// Mitsubishi GX Works2 project: TR3FB_sample_MultiConnection   PLC: Q03UDV
// TR3FBサンプルプログラム TCP/IP接続 2台同時制御

PROGRAM MAIN
VAR
  Connect_1 : P+TAKAYA-TR3-E_Connect;
  Connect_2 : P+TAKAYA-TR3-E_Connect;
  Disconnect_1 : P+TAKAYA-TR3-E_Disconnect;
  Disconnect_2 : P+TAKAYA-TR3-E_Disconnect;
  Inventory_1 : P+TAKAYA-TR3-E_Inventory;
  Inventory_2 : P+TAKAYA-TR3-E_Inventory;
  CallLEDBuzzer_1 : P+TAKAYA-TR3-E_CallLEDBuzzer;
  CallLEDBuzzer_2 : P+TAKAYA-TR3-E_CallLEDBuzzer;
  ReadBytes_1 : P+TAKAYA-TR3-E_ReadBytes;
  WriteBytes_1 : P+TAKAYA-TR3-E_WriteBytes;
  Response_1 : P+TAKAYA-TR3-E_Response;
  Response_2 : P+TAKAYA-TR3-E_Response;
END_VAR
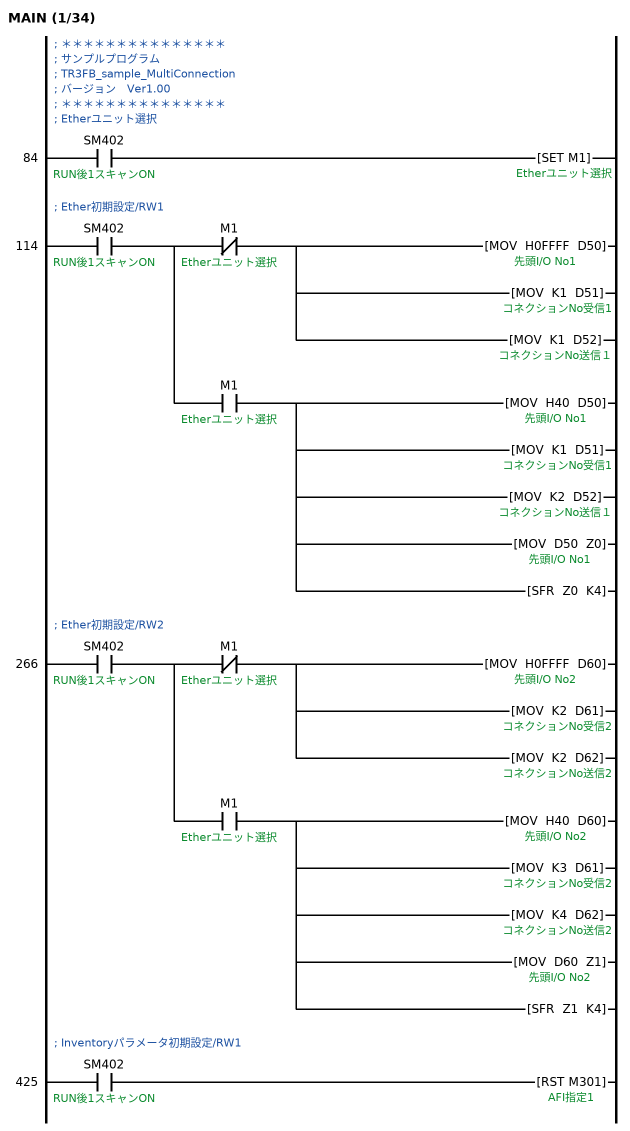
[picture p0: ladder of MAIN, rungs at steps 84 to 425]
; ＊＊＊＊＊＊＊＊＊＊＊＊＊＊＊
; サンプルプログラム
; TR3FB_sample_MultiConnection
; バージョン　Ver1.00
; ＊＊＊＊＊＊＊＊＊＊＊＊＊＊＊
; Etherユニット選択
84    LD      SM402  ; RUN後1スキャンON
      SET     M1  ; Etherユニット選択
        [note] OFF=内蔵Ether　ON=外付けEther
; Ether初期設定/RW1
114   LD      SM402  ; RUN後1スキャンON
      MPS
      ANI     M1  ; Etherユニット選択
      MOV     H0FFFF D50  ; 先頭I/O No1
        [note] 内蔵Ether先頭I/O
      MOV     K1 D51  ; コネクションNo受信1
        [note] 内蔵Ether受信コネクションNo
      MOV     K1 D52  ; コネクションNo送信１
        [note] 内蔵Ether送信コネクションNo
      MPP
      AND     M1  ; Etherユニット選択
      MOV     H40 D50
        [note] 外付Ether先頭I/O
      MOV     K1 D51
        [note] 外付Ether受信コネクションNo
      MOV     K2 D52
        [note] 外付Ether送信コネクションNo
      MOV     D50 Z0
        [note] EtherユニットI/Oアドレス取得
      SFR     Z0 K4
        [note] 4bit右シフトし上位側アドレス取得
; Ether初期設定/RW2
266   LD      SM402  ; RUN後1スキャンON
      MPS
      ANI     M1  ; Etherユニット選択
      MOV     H0FFFF D60  ; 先頭I/O No2
        [note] 内蔵Ether先頭I/O
      MOV     K2 D61  ; コネクションNo受信2
        [note] 内蔵Ether受信コネクションNo
      MOV     K2 D62  ; コネクションNo送信2
        [note] 内蔵Ether送信コネクションNo
      MPP
      AND     M1  ; Etherユニット選択
      MOV     H40 D60
        [note] 外付Ether先頭I/O
      MOV     K3 D61
        [note] 外付Ether受信コネクションNo
      MOV     K4 D62
        [note] 外付Ether送信コネクションNo
      MOV     D60 Z1
        [note] EtherユニットI/Oアドレス取得
      SFR     Z1 K4
        [note] 4bit右シフトし上位側アドレス取得
; Inventoryパラメータ初期設定/RW1
425   LD      SM402  ; RUN後1スキャンON
      RST     M301  ; AFI指定1
        [note] AFI指定：OFF=AFI値を指定しない
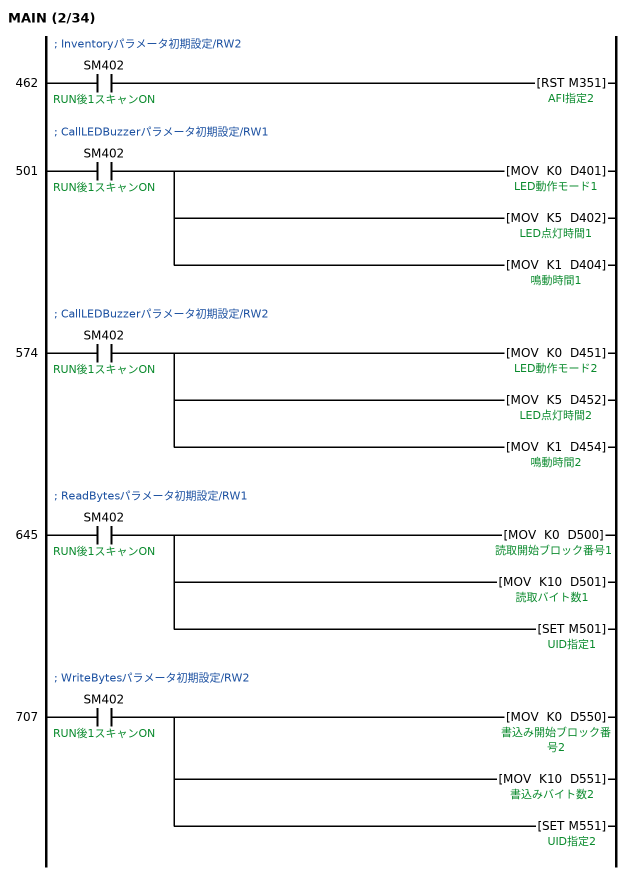
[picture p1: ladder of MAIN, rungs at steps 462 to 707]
; Inventoryパラメータ初期設定/RW2
462   LD      SM402  ; RUN後1スキャンON
      RST     M351  ; AFI指定2
        [note] AFI指定：OFF=AFI値を指定しない
; CallLEDBuzzerパラメータ初期設定/RW1
501   LD      SM402  ; RUN後1スキャンON
      MOV     K0 D401  ; LED動作モード1
        [note] LED動作モード=指定時間の点灯
      MOV     K5 D402  ; LED点灯時間1
        [note] LED点灯時間=1秒（200ms×5）
      MOV     K1 D404  ; 鳴動時間1
        [note] ブザー鳴動時間=鳴動する
; CallLEDBuzzerパラメータ初期設定/RW2
574   LD      SM402  ; RUN後1スキャンON
      MOV     K0 D451  ; LED動作モード2
        [note] LED動作モード=指定時間の点灯
      MOV     K5 D452  ; LED点灯時間2
        [note] LED点灯時間=1秒（200ms×5）
      MOV     K1 D454  ; 鳴動時間2
        [note] ブザー鳴動時間=鳴動する
; ReadBytesパラメータ初期設定/RW1
645   LD      SM402  ; RUN後1スキャンON
      MOV     K0 D500  ; 読取開始ブロック番号1
        [note] 読取開始ブロック番号=0
      MOV     K10 D501  ; 読取バイト数1
        [note] 読取バイト数=10
      SET     M501  ; UID指定1
        [note] UID指定：ON=UIDを指定する
; WriteBytesパラメータ初期設定/RW2
707   LD      SM402  ; RUN後1スキャンON
      MOV     K0 D550  ; 書込み開始ブロック番号2
        [note] 書込み開始ブロック番号=0
      MOV     K10 D551  ; 書込みバイト数2
        [note] 書込みバイト数=10
      SET     M551  ; UID指定2
        [note] UID指定：ON=UIDを指定する
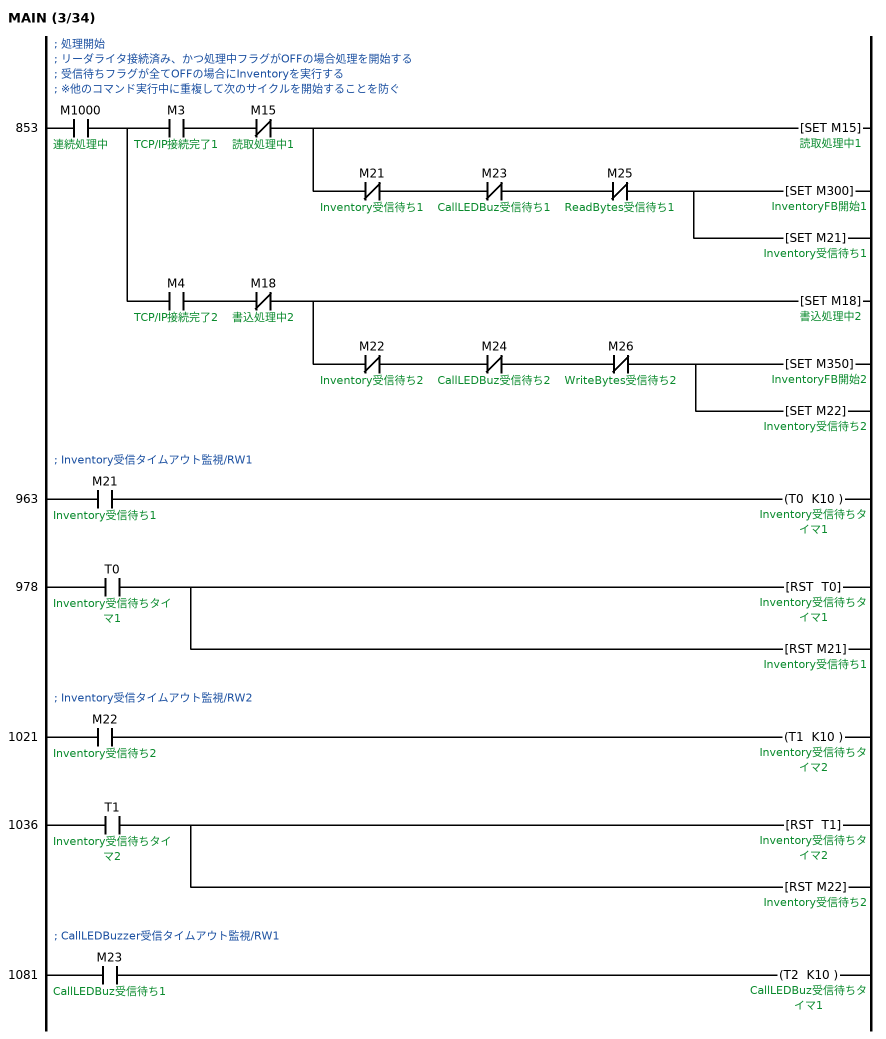
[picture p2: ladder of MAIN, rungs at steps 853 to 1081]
; 処理開始
; リーダライタ接続済み、かつ処理中フラグがOFFの場合処理を開始する
; 受信待ちフラグが全てOFFの場合にInventoryを実行する
; ※他のコマンド実行中に重複して次のサイクルを開始することを防ぐ
853   LD      M1000  ; 連続処理中
      MPS
      AND     M3  ; TCP/IP接続完了1
      ANI     M15  ; 読取処理中1
      SET     M15  ; 読取処理中1
        [note] 読取処理中1：セット
      ANI     M21  ; Inventory受信待ち1
      ANI     M23  ; CallLEDBuz受信待ち1
      ANI     M25  ; ReadBytes受信待ち1
      SET     M300  ; InventoryFB開始1
        [note] Inventory実行
      SET     M21  ; Inventory受信待ち1
        [note] Inventory受信待ち1：セット
      MPP
      AND     M4  ; TCP/IP接続完了2
      ANI     M18  ; 書込処理中2
      SET     M18  ; 書込処理中2
        [note] 書込処理中2：セット
      ANI     M22  ; Inventory受信待ち2
      ANI     M24  ; CallLEDBuz受信待ち2
      ANI     M26  ; WriteBytes受信待ち2
      SET     M350  ; InventoryFB開始2
        [note] Inventory実行
      SET     M22  ; Inventory受信待ち2
        [note] Inventory受信待ち2：セット
; Inventory受信タイムアウト監視/RW1
963   LD      M21  ; Inventory受信待ち1
      OUT     T0 K10  ; Inventory受信待ちタイマ1
        [note] タイマ1秒に設定
978   LD      T0  ; Inventory受信待ちタイマ1
      RST     T0  ; Inventory受信待ちタイマ1
        [note] タイマリセット
      RST     M21  ; Inventory受信待ち1
        [note] フラグリセット
; Inventory受信タイムアウト監視/RW2
1021  LD      M22  ; Inventory受信待ち2
      OUT     T1 K10  ; Inventory受信待ちタイマ2
        [note] タイマ1秒に設定
1036  LD      T1  ; Inventory受信待ちタイマ2
      RST     T1  ; Inventory受信待ちタイマ2
        [note] タイマリセット
      RST     M22  ; Inventory受信待ち2
        [note] フラグリセット
; CallLEDBuzzer受信タイムアウト監視/RW1
1081  LD      M23  ; CallLEDBuz受信待ち1
      OUT     T2 K10  ; CallLEDBuz受信待ちタイマ1
        [note] タイマ1秒に設定
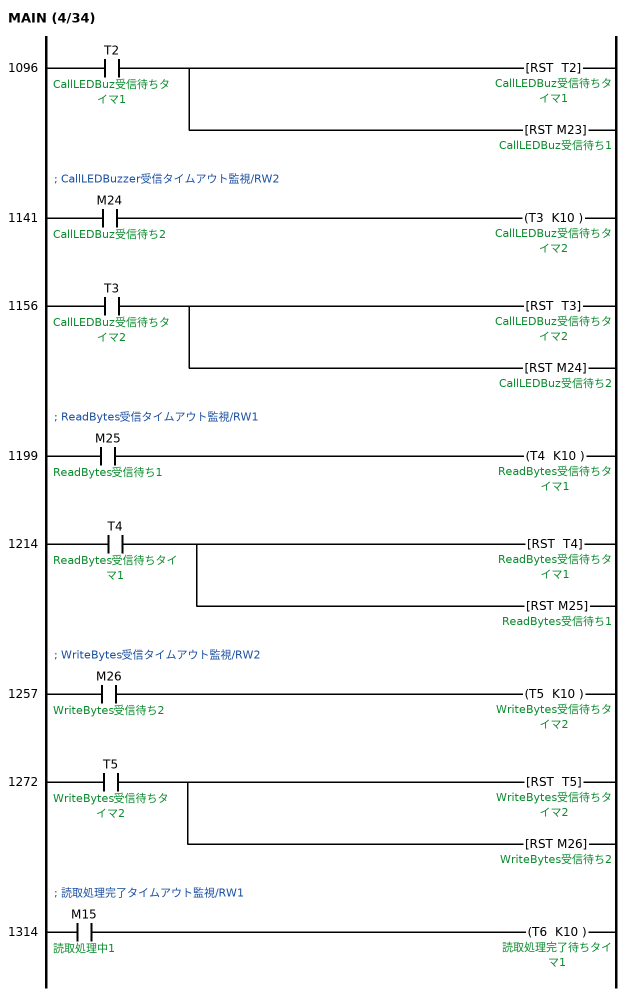
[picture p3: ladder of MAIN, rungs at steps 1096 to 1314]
1096  LD      T2  ; CallLEDBuz受信待ちタイマ1
      RST     T2  ; CallLEDBuz受信待ちタイマ1
        [note] タイマリセット
      RST     M23  ; CallLEDBuz受信待ち1
        [note] フラグリセット
; CallLEDBuzzer受信タイムアウト監視/RW2
1141  LD      M24  ; CallLEDBuz受信待ち2
      OUT     T3 K10  ; CallLEDBuz受信待ちタイマ2
        [note] タイマ1秒に設定
1156  LD      T3  ; CallLEDBuz受信待ちタイマ2
      RST     T3  ; CallLEDBuz受信待ちタイマ2
        [note] タイマリセット
      RST     M24  ; CallLEDBuz受信待ち2
        [note] フラグリセット
; ReadBytes受信タイムアウト監視/RW1
1199  LD      M25  ; ReadBytes受信待ち1
      OUT     T4 K10  ; ReadBytes受信待ちタイマ1
        [note] タイマ1秒に設定
1214  LD      T4  ; ReadBytes受信待ちタイマ1
      RST     T4  ; ReadBytes受信待ちタイマ1
        [note] タイマリセット
      RST     M25  ; ReadBytes受信待ち1
        [note] フラグリセット
; WriteBytes受信タイムアウト監視/RW2
1257  LD      M26  ; WriteBytes受信待ち2
      OUT     T5 K10  ; WriteBytes受信待ちタイマ2
        [note] タイマ1秒に設定
1272  LD      T5  ; WriteBytes受信待ちタイマ2
      RST     T5  ; WriteBytes受信待ちタイマ2
        [note] タイマリセット
      RST     M26  ; WriteBytes受信待ち2
        [note] フラグリセット
; 読取処理完了タイムアウト監視/RW1
1314  LD      M15  ; 読取処理中1
      OUT     T6 K10  ; 読取処理完了待ちタイマ1
        [note] タイマ1秒に設定
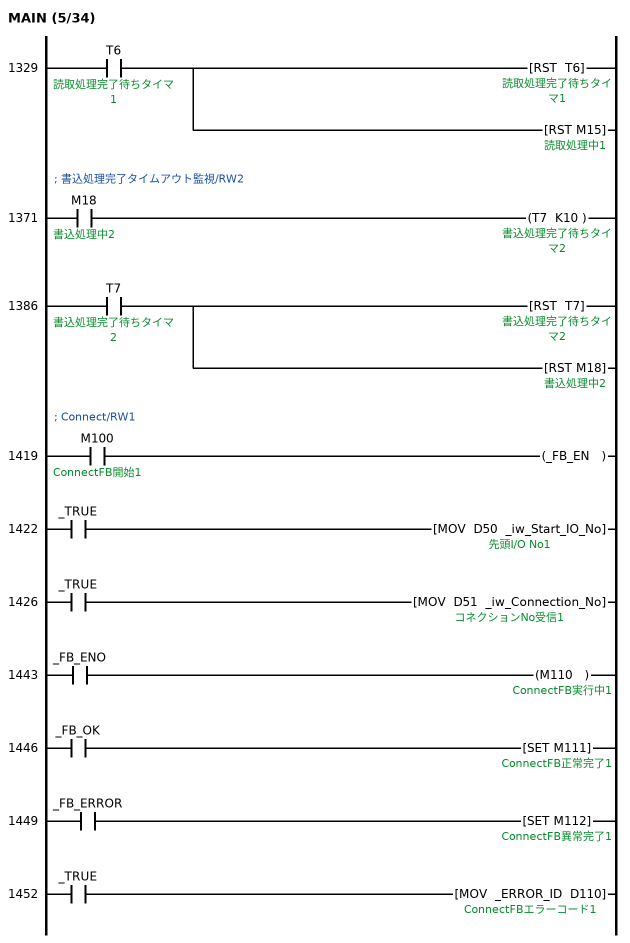
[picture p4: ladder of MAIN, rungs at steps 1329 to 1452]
1329  LD      T6  ; 読取処理完了待ちタイマ1
      RST     T6  ; 読取処理完了待ちタイマ1
        [note] タイマリセット
      RST     M15  ; 読取処理中1
        [note] フラグリセット
; 書込処理完了タイムアウト監視/RW2
1371  LD      M18  ; 書込処理中2
      OUT     T7 K10  ; 書込処理完了待ちタイマ2
        [note] タイマ1秒に設定
1386  LD      T7  ; 書込処理完了待ちタイマ2
      RST     T7  ; 書込処理完了待ちタイマ2
        [note] タイマリセット
      RST     M18  ; 書込処理中2
        [note] フラグリセット
; FB BLK START P+TAKAYA-TR3-E_Connect(Connect_1)
; Connect/RW1
1419  LD      M100  ; ConnectFB開始1
      OUT     _FB_EN
1422  LD      _TRUE
      MOV     D50 _iw_Start_IO_No
1426  LD      _TRUE
      MOV     D51 _iw_Connection_No
; FB START
; FB_NAME P+TAKAYA-TR3-E_Connect
; INSTANCE_NAME Connect_1
; FB IN_B:FB_EN
; FB OUT_FB_ENO:B
; FB IN_W:iw_Start_IO_No
; FB OUT_FB_OK:B
; FB IN_W:iw_Connection_No
; FB OUT_FB_ERROR:B
; FB OUT_ERROR_ID:W
; FB OUT_ob_UNIT_ERROR:B
; FB OUT_ow_UNIT_ERR_CODE:W
; FB END
1443  LD      _FB_ENO
      OUT     M110  ; ConnectFB実行中1
1446  LD      _FB_OK
      SET     M111  ; ConnectFB正常完了1
1449  LD      _FB_ERROR
      SET     M112  ; ConnectFB異常完了1
1452  LD      _TRUE
      MOV     _ERROR_ID D110  ; ConnectFBエラーコード1
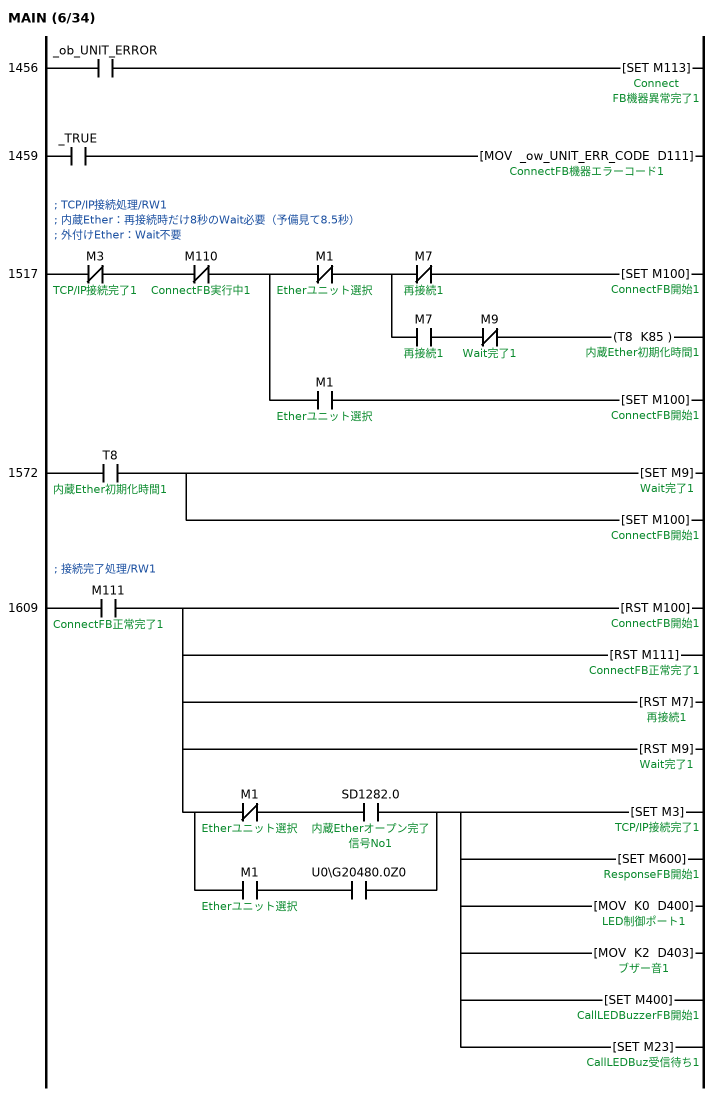
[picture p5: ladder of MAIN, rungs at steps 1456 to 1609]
1456  LD      _ob_UNIT_ERROR
      SET     M113  ; ConnectFB機器異常完了1
1459  LD      _TRUE
      MOV     _ow_UNIT_ERR_CODE D111  ; ConnectFB機器エラーコード1
; FB BLK END
; TCP/IP接続処理/RW1
; 内蔵Ether：再接続時だけ8秒のWait必要（予備見て8.5秒）
; 外付けEther：Wait不要
1517  LDI     M3  ; TCP/IP接続完了1
      ANI     M110  ; ConnectFB実行中1
      MPS
      ANI     M1  ; Etherユニット選択
      MPS
      ANI     M7  ; 再接続1
      SET     M100  ; ConnectFB開始1
        [note] 内蔵Ether初回接続処理
      MPP
      AND     M7  ; 再接続1
      ANI     M9  ; Wait完了1
      OUT     T8 K85  ; 内蔵Ether初期化時間1
        [note] 内蔵Ether再接続Wait処理
      MPP
      AND     M1  ; Etherユニット選択
      SET     M100  ; ConnectFB開始1
        [note] 外付Ether接続処理
1572  LD      T8  ; 内蔵Ether初期化時間1
      SET     M9  ; Wait完了1
        [note] Wait完了フラグをセット
      SET     M100  ; ConnectFB開始1
        [note] Wait完了後に再接続
; 接続完了処理/RW1
1609  LD      M111  ; ConnectFB正常完了1
      RST     M100  ; ConnectFB開始1
        [note] FB動作停止
      RST     M111  ; ConnectFB正常完了1
        [note] フラグリセット
      RST     M7  ; 再接続1
        [note] フラグリセット
      RST     M9  ; Wait完了1
        [note] フラグリセット
      LDI     M1  ; Etherユニット選択
      AND     SD1282.0  ; 内蔵Etherオープン完了信号No1
      LD      M1  ; Etherユニット選択
      AND     U0\G20480.0Z0
      ORB
      ANB
      SET     M3  ; TCP/IP接続完了1
        [note] TCP/IP接続完了：セット
      SET     M600  ; ResponseFB開始1
        [note] 受信処理開始
      MOV     K0 D400  ; LED制御ポート1
        [note] LED制御ポート=0/LED制御なし
      MOV     K2 D403  ; ブザー音1
        [note] ブザー音=2/ピッピー
      SET     M400  ; CallLEDBuzzerFB開始1
        [note] CallLEDBuzzer実行
      SET     M23  ; CallLEDBuz受信待ち1
        [note] CallLEDBuz受信待ち1：セット
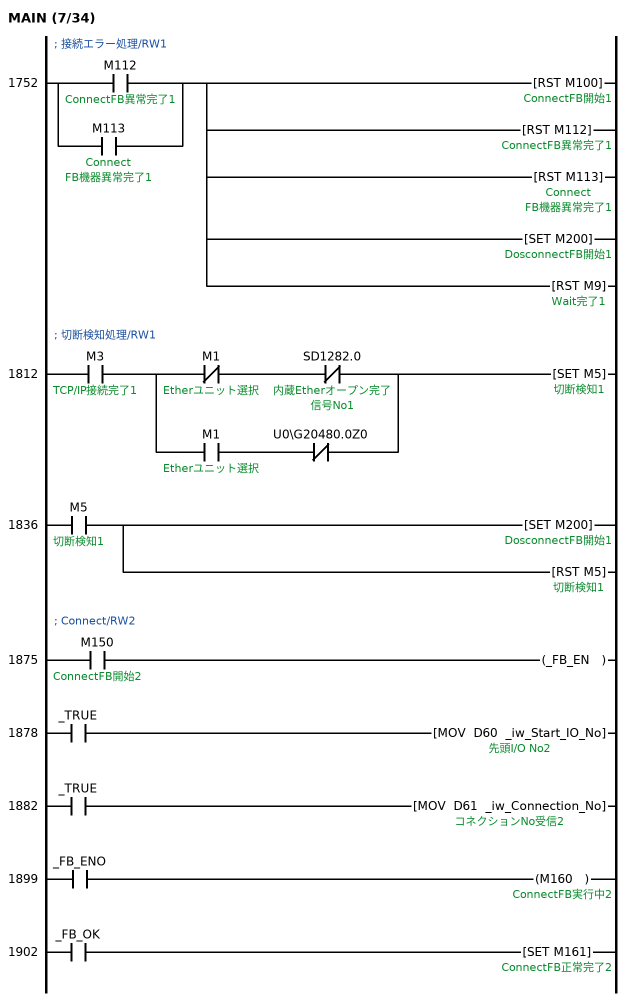
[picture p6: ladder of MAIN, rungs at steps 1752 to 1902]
; 接続エラー処理/RW1
1752  LD      M112  ; ConnectFB異常完了1
      OR      M113  ; ConnectFB機器異常完了1
      RST     M100  ; ConnectFB開始1
        [note] FB動作停止
      RST     M112  ; ConnectFB異常完了1
        [note] フラグリセット
      RST     M113  ; ConnectFB機器異常完了1
        [note] フラグリセット
      SET     M200  ; DosconnectFB開始1
        [note] 切断処理を実行
      RST     M9  ; Wait完了1
        [note] フラグリセット
; 切断検知処理/RW1
1812  LD      M3  ; TCP/IP接続完了1
      LDI     M1  ; Etherユニット選択
      ANI     SD1282.0  ; 内蔵Etherオープン完了信号No1
      LD      M1  ; Etherユニット選択
      ANI     U0\G20480.0Z0
      ORB
      ANB
      SET     M5  ; 切断検知1
        [note] 切断検知フラグをセット
1836  LD      M5  ; 切断検知1
      SET     M200  ; DosconnectFB開始1
        [note] 切断処理（再接続するために必要）
      RST     M5  ; 切断検知1
        [note] フラグリセット
; FB BLK START P+TAKAYA-TR3-E_Connect(Connect_2)
; Connect/RW2
1875  LD      M150  ; ConnectFB開始2
      OUT     _FB_EN
1878  LD      _TRUE
      MOV     D60 _iw_Start_IO_No
1882  LD      _TRUE
      MOV     D61 _iw_Connection_No
; FB START
; FB_NAME P+TAKAYA-TR3-E_Connect
; INSTANCE_NAME Connect_2
; FB IN_B:FB_EN
; FB OUT_FB_ENO:B
; FB IN_W:iw_Start_IO_No
; FB OUT_FB_OK:B
; FB IN_W:iw_Connection_No
; FB OUT_FB_ERROR:B
; FB OUT_ERROR_ID:W
; FB OUT_ob_UNIT_ERROR:B
; FB OUT_ow_UNIT_ERR_CODE:W
; FB END
1899  LD      _FB_ENO
      OUT     M160  ; ConnectFB実行中2
1902  LD      _FB_OK
      SET     M161  ; ConnectFB正常完了2
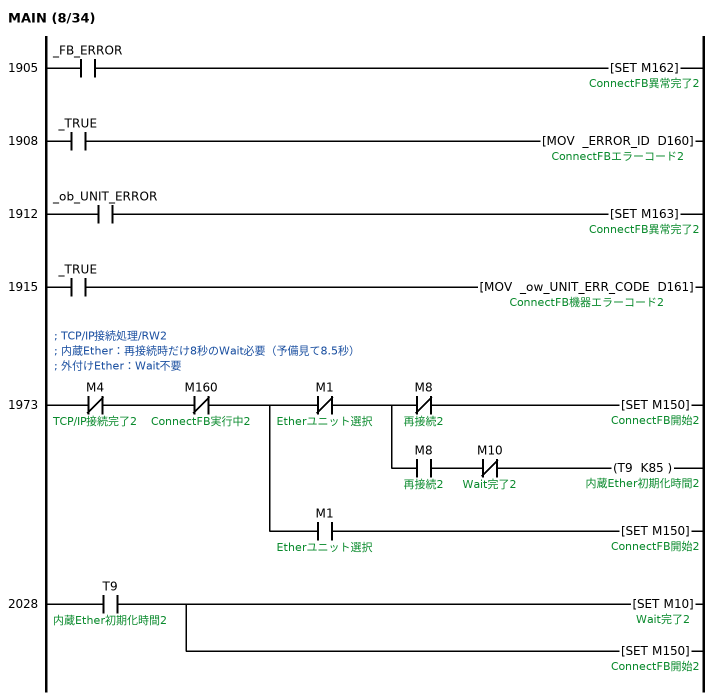
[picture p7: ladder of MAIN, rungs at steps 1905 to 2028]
1905  LD      _FB_ERROR
      SET     M162  ; ConnectFB異常完了2
1908  LD      _TRUE
      MOV     _ERROR_ID D160  ; ConnectFBエラーコード2
1912  LD      _ob_UNIT_ERROR
      SET     M163  ; ConnectFB異常完了2
1915  LD      _TRUE
      MOV     _ow_UNIT_ERR_CODE D161  ; ConnectFB機器エラーコード2
; FB BLK END
; TCP/IP接続処理/RW2
; 内蔵Ether：再接続時だけ8秒のWait必要（予備見て8.5秒）
; 外付けEther：Wait不要
1973  LDI     M4  ; TCP/IP接続完了2
      ANI     M160  ; ConnectFB実行中2
      MPS
      ANI     M1  ; Etherユニット選択
      MPS
      ANI     M8  ; 再接続2
      SET     M150  ; ConnectFB開始2
        [note] 内蔵Ether初回接続処理
      MPP
      AND     M8  ; 再接続2
      ANI     M10  ; Wait完了2
      OUT     T9 K85  ; 内蔵Ether初期化時間2
        [note] 内蔵Ether再接続Wait処理
      MPP
      AND     M1  ; Etherユニット選択
      SET     M150  ; ConnectFB開始2
        [note] 外付Ether接続処理
2028  LD      T9  ; 内蔵Ether初期化時間2
      SET     M10  ; Wait完了2
        [note] Wait完了フラグをセット
      SET     M150  ; ConnectFB開始2
        [note] Wait完了後に再接続
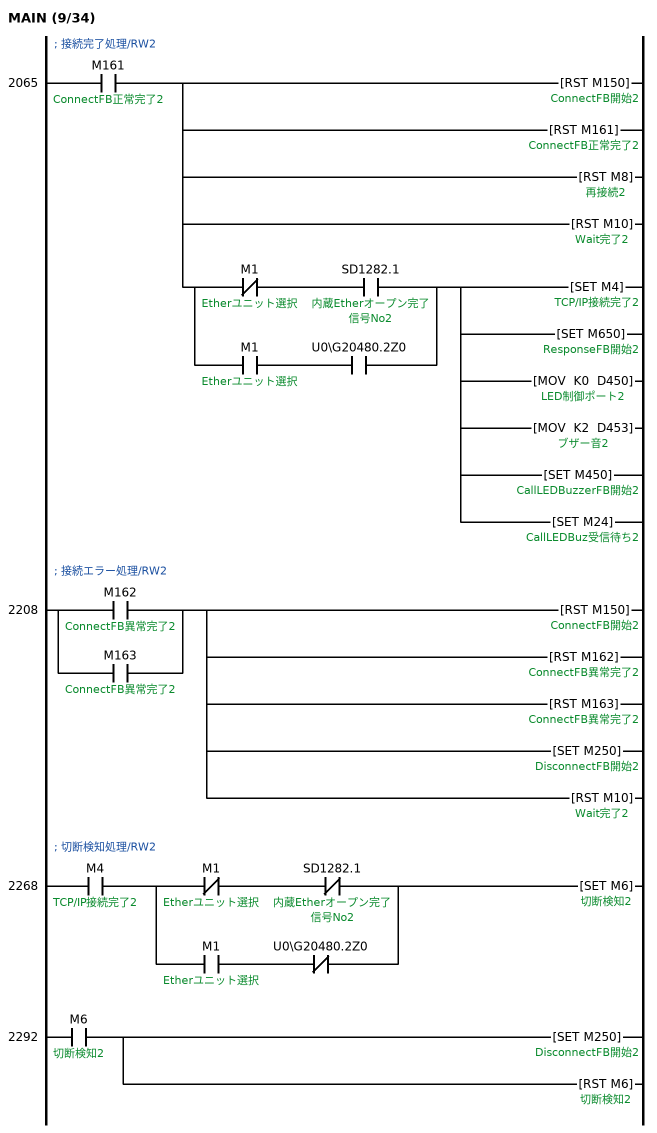
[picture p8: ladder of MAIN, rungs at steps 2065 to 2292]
; 接続完了処理/RW2
2065  LD      M161  ; ConnectFB正常完了2
      RST     M150  ; ConnectFB開始2
        [note] FB動作停止
      RST     M161  ; ConnectFB正常完了2
        [note] フラグリセット
      RST     M8  ; 再接続2
        [note] フラグリセット
      RST     M10  ; Wait完了2
        [note] フラグリセット
      LDI     M1  ; Etherユニット選択
      AND     SD1282.1  ; 内蔵Etherオープン完了信号No2
      LD      M1  ; Etherユニット選択
      AND     U0\G20480.2Z0
      ORB
      ANB
      SET     M4  ; TCP/IP接続完了2
        [note] TCP/IP接続完了：セット
      SET     M650  ; ResponseFB開始2
        [note] 受信処理開始
      MOV     K0 D450  ; LED制御ポート2
        [note] LED制御ポート=0/LED制御なし
      MOV     K2 D453  ; ブザー音2
        [note] ブザー音=2/ピッピー
      SET     M450  ; CallLEDBuzzerFB開始2
        [note] CallLEDBuzzer実行
      SET     M24  ; CallLEDBuz受信待ち2
        [note] CallLEDBuz受信待ち2：セット
; 接続エラー処理/RW2
2208  LD      M162  ; ConnectFB異常完了2
      OR      M163  ; ConnectFB異常完了2
      RST     M150  ; ConnectFB開始2
        [note] FB動作停止
      RST     M162  ; ConnectFB異常完了2
        [note] フラグリセット
      RST     M163  ; ConnectFB異常完了2
        [note] フラグリセット
      SET     M250  ; DisconnectFB開始2
        [note] 切断処理を実行
      RST     M10  ; Wait完了2
        [note] フラグリセット
; 切断検知処理/RW2
2268  LD      M4  ; TCP/IP接続完了2
      LDI     M1  ; Etherユニット選択
      ANI     SD1282.1  ; 内蔵Etherオープン完了信号No2
      LD      M1  ; Etherユニット選択
      ANI     U0\G20480.2Z0
      ORB
      ANB
      SET     M6  ; 切断検知2
        [note] 切断検知フラグをセット
2292  LD      M6  ; 切断検知2
      SET     M250  ; DisconnectFB開始2
        [note] 切断処理（再接続するために必要）
      RST     M6  ; 切断検知2
        [note] フラグリセット
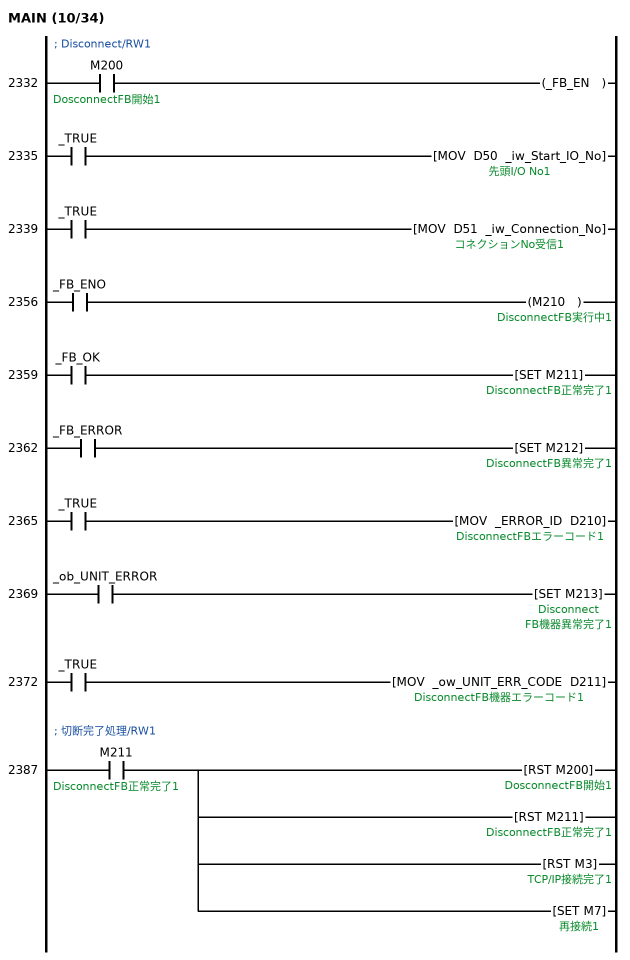
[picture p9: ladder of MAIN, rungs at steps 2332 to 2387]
; FB BLK START P+TAKAYA-TR3-E_Disconnect(Disconnect_1)
; Disconnect/RW1
2332  LD      M200  ; DosconnectFB開始1
      OUT     _FB_EN
2335  LD      _TRUE
      MOV     D50 _iw_Start_IO_No
2339  LD      _TRUE
      MOV     D51 _iw_Connection_No
; FB START
; FB_NAME P+TAKAYA-TR3-E_Disconnect
; INSTANCE_NAME Disconnect_1
; FB IN_B:FB_EN
; FB OUT_FB_ENO:B
; FB IN_W:iw_Start_IO_No
; FB OUT_FB_OK:B
; FB IN_W:iw_Connection_No
; FB OUT_FB_ERROR:B
; FB OUT_ERROR_ID:W
; FB OUT_ob_UNIT_ERROR:B
; FB OUT_ow_UNIT_ERR_CODE:W
; FB END
2356  LD      _FB_ENO
      OUT     M210  ; DisconnectFB実行中1
2359  LD      _FB_OK
      SET     M211  ; DisconnectFB正常完了1
2362  LD      _FB_ERROR
      SET     M212  ; DisconnectFB異常完了1
2365  LD      _TRUE
      MOV     _ERROR_ID D210  ; DisconnectFBエラーコード1
2369  LD      _ob_UNIT_ERROR
      SET     M213  ; DisconnectFB機器異常完了1
2372  LD      _TRUE
      MOV     _ow_UNIT_ERR_CODE D211  ; DisconnectFB機器エラーコード1
; FB BLK END
; 切断完了処理/RW1
2387  LD      M211  ; DisconnectFB正常完了1
      RST     M200  ; DosconnectFB開始1
        [note] FB動作停止
      RST     M211  ; DisconnectFB正常完了1
        [note] フラグリセット
      RST     M3  ; TCP/IP接続完了1
        [note] フラグリセット
      SET     M7  ; 再接続1
        [note] 再接続：セット
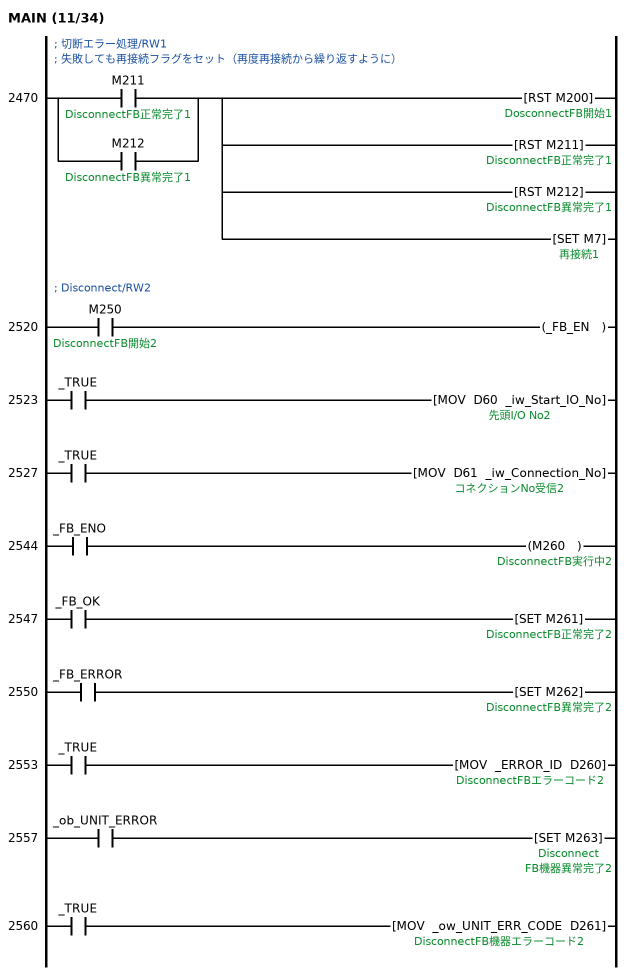
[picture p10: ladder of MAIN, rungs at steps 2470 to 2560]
; 切断エラー処理/RW1
; 失敗しても再接続フラグをセット（再度再接続から繰り返すように）
2470  LD      M211  ; DisconnectFB正常完了1
      OR      M212  ; DisconnectFB異常完了1
      RST     M200  ; DosconnectFB開始1
        [note] FB動作停止
      RST     M211  ; DisconnectFB正常完了1
        [note] フラグリセット
      RST     M212  ; DisconnectFB異常完了1
        [note] フラグリセット
      SET     M7  ; 再接続1
        [note] 再接続：セット
; FB BLK START P+TAKAYA-TR3-E_Disconnect(Disconnect_2)
; Disconnect/RW2
2520  LD      M250  ; DisconnectFB開始2
      OUT     _FB_EN
2523  LD      _TRUE
      MOV     D60 _iw_Start_IO_No
2527  LD      _TRUE
      MOV     D61 _iw_Connection_No
; FB START
; FB_NAME P+TAKAYA-TR3-E_Disconnect
; INSTANCE_NAME Disconnect_2
; FB IN_B:FB_EN
; FB OUT_FB_ENO:B
; FB IN_W:iw_Start_IO_No
; FB OUT_FB_OK:B
; FB IN_W:iw_Connection_No
; FB OUT_FB_ERROR:B
; FB OUT_ERROR_ID:W
; FB OUT_ob_UNIT_ERROR:B
; FB OUT_ow_UNIT_ERR_CODE:W
; FB END
2544  LD      _FB_ENO
      OUT     M260  ; DisconnectFB実行中2
2547  LD      _FB_OK
      SET     M261  ; DisconnectFB正常完了2
2550  LD      _FB_ERROR
      SET     M262  ; DisconnectFB異常完了2
2553  LD      _TRUE
      MOV     _ERROR_ID D260  ; DisconnectFBエラーコード2
2557  LD      _ob_UNIT_ERROR
      SET     M263  ; DisconnectFB機器異常完了2
2560  LD      _TRUE
      MOV     _ow_UNIT_ERR_CODE D261  ; DisconnectFB機器エラーコード2
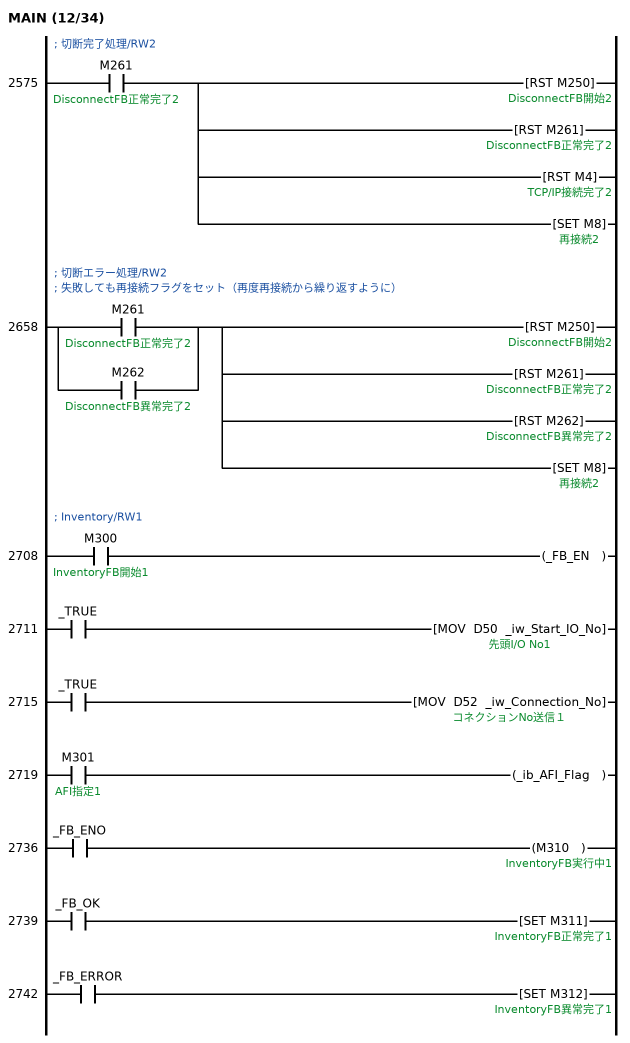
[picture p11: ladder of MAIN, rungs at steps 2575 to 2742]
; FB BLK END
; 切断完了処理/RW2
2575  LD      M261  ; DisconnectFB正常完了2
      RST     M250  ; DisconnectFB開始2
        [note] FB動作停止
      RST     M261  ; DisconnectFB正常完了2
        [note] フラグリセット
      RST     M4  ; TCP/IP接続完了2
        [note] フラグリセット
      SET     M8  ; 再接続2
        [note] 再接続：セット
; 切断エラー処理/RW2
; 失敗しても再接続フラグをセット（再度再接続から繰り返すように）
2658  LD      M261  ; DisconnectFB正常完了2
      OR      M262  ; DisconnectFB異常完了2
      RST     M250  ; DisconnectFB開始2
        [note] FB動作停止
      RST     M261  ; DisconnectFB正常完了2
        [note] フラグリセット
      RST     M262  ; DisconnectFB異常完了2
        [note] フラグリセット
      SET     M8  ; 再接続2
        [note] 再接続：セット
; FB BLK START P+TAKAYA-TR3-E_Inventory(Inventory_1)
; Inventory/RW1
2708  LD      M300  ; InventoryFB開始1
      OUT     _FB_EN
2711  LD      _TRUE
      MOV     D50 _iw_Start_IO_No
2715  LD      _TRUE
      MOV     D52 _iw_Connection_No
2719  LD      M301  ; AFI指定1
      OUT     _ib_AFI_Flag
; FB START
; FB_NAME P+TAKAYA-TR3-E_Inventory
; INSTANCE_NAME Inventory_1
; FB IN_B:FB_EN
; FB OUT_FB_ENO:B
; FB IN_W:iw_Start_IO_No
; FB OUT_FB_OK:B
; FB IN_W:iw_Connection_No
; FB OUT_FB_ERROR:B
; FB IN_B:ib_AFI_Flag
; FB OUT_ERROR_ID:W
; FB OUT_ob_UNIT_ERROR:B
; FB OUT_ow_UNIT_ERR_CODE:W
; FB END
2736  LD      _FB_ENO
      OUT     M310  ; InventoryFB実行中1
2739  LD      _FB_OK
      SET     M311  ; InventoryFB正常完了1
2742  LD      _FB_ERROR
      SET     M312  ; InventoryFB異常完了1
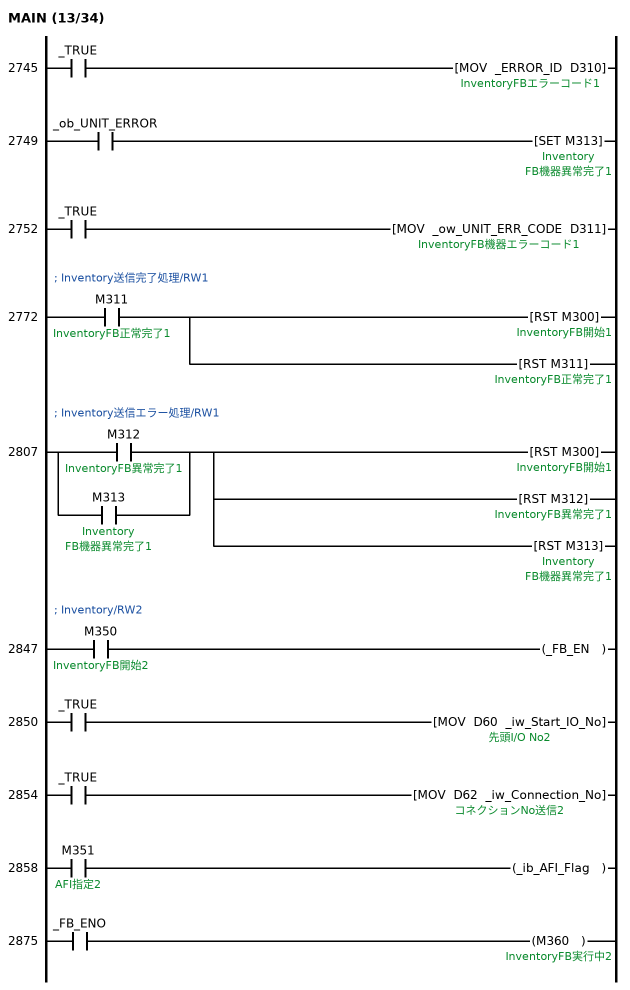
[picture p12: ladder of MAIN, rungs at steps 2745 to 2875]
2745  LD      _TRUE
      MOV     _ERROR_ID D310  ; InventoryFBエラーコード1
2749  LD      _ob_UNIT_ERROR
      SET     M313  ; InventoryFB機器異常完了1
2752  LD      _TRUE
      MOV     _ow_UNIT_ERR_CODE D311  ; InventoryFB機器エラーコード1
; FB BLK END
; Inventory送信完了処理/RW1
2772  LD      M311  ; InventoryFB正常完了1
      RST     M300  ; InventoryFB開始1
        [note] FB動作停止
      RST     M311  ; InventoryFB正常完了1
        [note] フラグリセット
; Inventory送信エラー処理/RW1
2807  LD      M312  ; InventoryFB異常完了1
      OR      M313  ; InventoryFB機器異常完了1
      RST     M300  ; InventoryFB開始1
        [note] FB動作停止
      RST     M312  ; InventoryFB異常完了1
        [note] フラグリセット
      RST     M313  ; InventoryFB機器異常完了1
        [note] フラグリセット
; FB BLK START P+TAKAYA-TR3-E_Inventory(Inventory_2)
; Inventory/RW2
2847  LD      M350  ; InventoryFB開始2
      OUT     _FB_EN
2850  LD      _TRUE
      MOV     D60 _iw_Start_IO_No
2854  LD      _TRUE
      MOV     D62 _iw_Connection_No
2858  LD      M351  ; AFI指定2
      OUT     _ib_AFI_Flag
; FB START
; FB_NAME P+TAKAYA-TR3-E_Inventory
; INSTANCE_NAME Inventory_2
; FB IN_B:FB_EN
; FB OUT_FB_ENO:B
; FB IN_W:iw_Start_IO_No
; FB OUT_FB_OK:B
; FB IN_W:iw_Connection_No
; FB OUT_FB_ERROR:B
; FB IN_B:ib_AFI_Flag
; FB OUT_ERROR_ID:W
; FB OUT_ob_UNIT_ERROR:B
; FB OUT_ow_UNIT_ERR_CODE:W
; FB END
2875  LD      _FB_ENO
      OUT     M360  ; InventoryFB実行中2
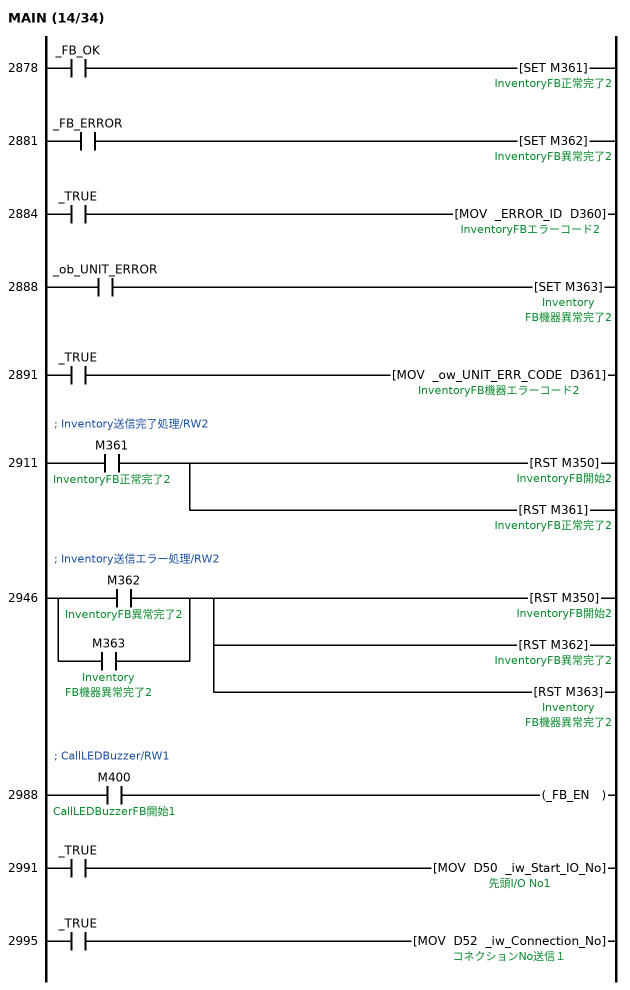
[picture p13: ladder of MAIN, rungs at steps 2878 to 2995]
2878  LD      _FB_OK
      SET     M361  ; InventoryFB正常完了2
2881  LD      _FB_ERROR
      SET     M362  ; InventoryFB異常完了2
2884  LD      _TRUE
      MOV     _ERROR_ID D360  ; InventoryFBエラーコード2
2888  LD      _ob_UNIT_ERROR
      SET     M363  ; InventoryFB機器異常完了2
2891  LD      _TRUE
      MOV     _ow_UNIT_ERR_CODE D361  ; InventoryFB機器エラーコード2
; FB BLK END
; Inventory送信完了処理/RW2
2911  LD      M361  ; InventoryFB正常完了2
      RST     M350  ; InventoryFB開始2
        [note] FB動作停止
      RST     M361  ; InventoryFB正常完了2
        [note] フラグリセット
; Inventory送信エラー処理/RW2
2946  LD      M362  ; InventoryFB異常完了2
      OR      M363  ; InventoryFB機器異常完了2
      RST     M350  ; InventoryFB開始2
        [note] FB動作停止
      RST     M362  ; InventoryFB異常完了2
        [note] フラグリセット
      RST     M363  ; InventoryFB機器異常完了2
        [note] フラグリセット
; FB BLK START P+TAKAYA-TR3-E_CallLEDBuzzer(CallLEDBuzzer_1)
; CallLEDBuzzer/RW1
2988  LD      M400  ; CallLEDBuzzerFB開始1
      OUT     _FB_EN
2991  LD      _TRUE
      MOV     D50 _iw_Start_IO_No
2995  LD      _TRUE
      MOV     D52 _iw_Connection_No
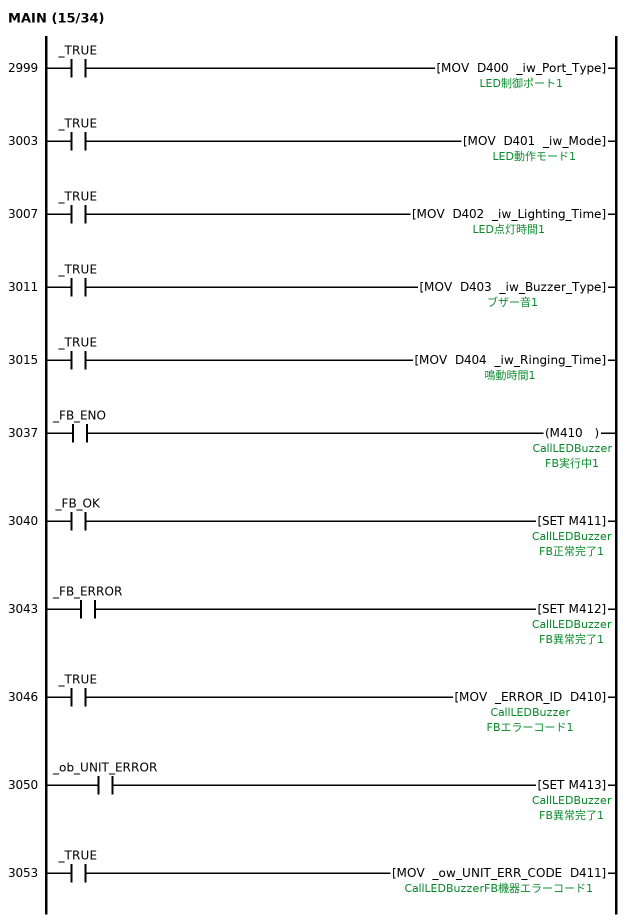
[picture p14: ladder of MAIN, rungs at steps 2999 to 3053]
2999  LD      _TRUE
      MOV     D400 _iw_Port_Type
3003  LD      _TRUE
      MOV     D401 _iw_Mode
3007  LD      _TRUE
      MOV     D402 _iw_Lighting_Time
3011  LD      _TRUE
      MOV     D403 _iw_Buzzer_Type
3015  LD      _TRUE
      MOV     D404 _iw_Ringing_Time
; FB START
; FB_NAME P+TAKAYA-TR3-E_CallLEDBuzzer
; INSTANCE_NAME CallLEDBuzzer_1
; FB IN_B:FB_EN
; FB OUT_FB_ENO:B
; FB IN_W:iw_Start_IO_No
; FB OUT_FB_OK:B
; FB IN_W:iw_Connection_No
; FB OUT_FB_ERROR:B
; FB IN_W:iw_Port_Type
; FB OUT_ERROR_ID:W
; FB IN_W:iw_Mode
; FB OUT_ob_UNIT_ERROR:B
; FB IN_W:iw_Lighting_Time
; FB OUT_ow_UNIT_ERR_CODE:W
; FB IN_W:iw_Buzzer_Type
; FB IN_W:iw_Ringing_Time
; FB END
3037  LD      _FB_ENO
      OUT     M410  ; CallLEDBuzzerFB実行中1
3040  LD      _FB_OK
      SET     M411  ; CallLEDBuzzerFB正常完了1
3043  LD      _FB_ERROR
      SET     M412  ; CallLEDBuzzerFB異常完了1
3046  LD      _TRUE
      MOV     _ERROR_ID D410  ; CallLEDBuzzerFBエラーコード1
3050  LD      _ob_UNIT_ERROR
      SET     M413  ; CallLEDBuzzerFB異常完了1
3053  LD      _TRUE
      MOV     _ow_UNIT_ERR_CODE D411  ; CallLEDBuzzerFB機器エラーコード1
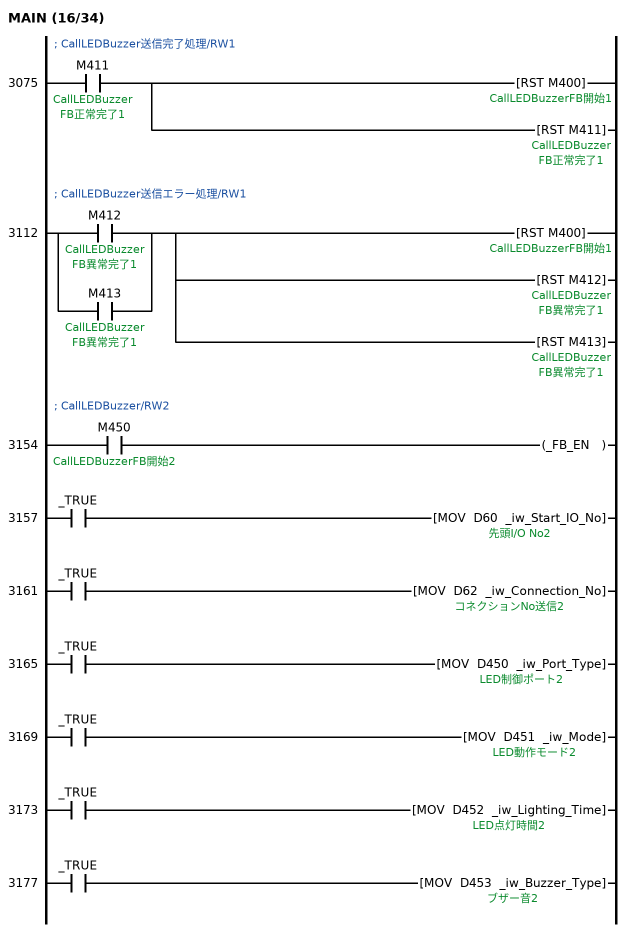
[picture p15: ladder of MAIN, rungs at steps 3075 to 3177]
; FB BLK END
; CallLEDBuzzer送信完了処理/RW1
3075  LD      M411  ; CallLEDBuzzerFB正常完了1
      RST     M400  ; CallLEDBuzzerFB開始1
        [note] FB動作停止
      RST     M411  ; CallLEDBuzzerFB正常完了1
        [note] フラグリセット
; CallLEDBuzzer送信エラー処理/RW1
3112  LD      M412  ; CallLEDBuzzerFB異常完了1
      OR      M413  ; CallLEDBuzzerFB異常完了1
      RST     M400  ; CallLEDBuzzerFB開始1
        [note] FB動作停止
      RST     M412  ; CallLEDBuzzerFB異常完了1
        [note] フラグリセット
      RST     M413  ; CallLEDBuzzerFB異常完了1
        [note] フラグリセット
; FB BLK START P+TAKAYA-TR3-E_CallLEDBuzzer(CallLEDBuzzer_2)
; CallLEDBuzzer/RW2
3154  LD      M450  ; CallLEDBuzzerFB開始2
      OUT     _FB_EN
3157  LD      _TRUE
      MOV     D60 _iw_Start_IO_No
3161  LD      _TRUE
      MOV     D62 _iw_Connection_No
3165  LD      _TRUE
      MOV     D450 _iw_Port_Type
3169  LD      _TRUE
      MOV     D451 _iw_Mode
3173  LD      _TRUE
      MOV     D452 _iw_Lighting_Time
3177  LD      _TRUE
      MOV     D453 _iw_Buzzer_Type
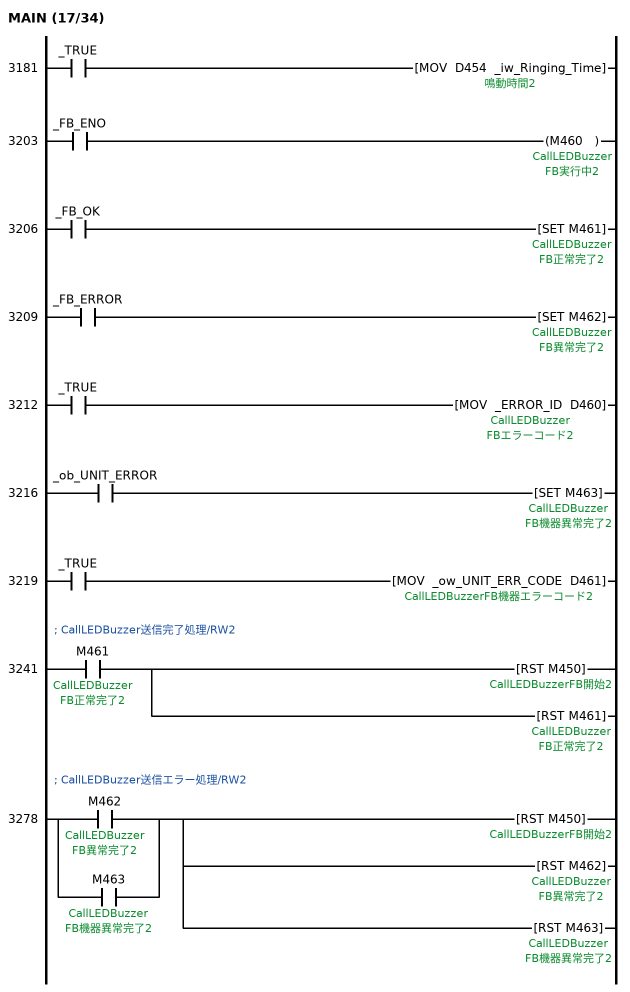
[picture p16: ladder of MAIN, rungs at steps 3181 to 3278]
3181  LD      _TRUE
      MOV     D454 _iw_Ringing_Time
; FB START
; FB_NAME P+TAKAYA-TR3-E_CallLEDBuzzer
; INSTANCE_NAME CallLEDBuzzer_2
; FB IN_B:FB_EN
; FB OUT_FB_ENO:B
; FB IN_W:iw_Start_IO_No
; FB OUT_FB_OK:B
; FB IN_W:iw_Connection_No
; FB OUT_FB_ERROR:B
; FB IN_W:iw_Port_Type
; FB OUT_ERROR_ID:W
; FB IN_W:iw_Mode
; FB OUT_ob_UNIT_ERROR:B
; FB IN_W:iw_Lighting_Time
; FB OUT_ow_UNIT_ERR_CODE:W
; FB IN_W:iw_Buzzer_Type
; FB IN_W:iw_Ringing_Time
; FB END
3203  LD      _FB_ENO
      OUT     M460  ; CallLEDBuzzerFB実行中2
3206  LD      _FB_OK
      SET     M461  ; CallLEDBuzzerFB正常完了2
3209  LD      _FB_ERROR
      SET     M462  ; CallLEDBuzzerFB異常完了2
3212  LD      _TRUE
      MOV     _ERROR_ID D460  ; CallLEDBuzzerFBエラーコード2
3216  LD      _ob_UNIT_ERROR
      SET     M463  ; CallLEDBuzzerFB機器異常完了2
3219  LD      _TRUE
      MOV     _ow_UNIT_ERR_CODE D461  ; CallLEDBuzzerFB機器エラーコード2
; FB BLK END
; CallLEDBuzzer送信完了処理/RW2
3241  LD      M461  ; CallLEDBuzzerFB正常完了2
      RST     M450  ; CallLEDBuzzerFB開始2
        [note] FB動作停止
      RST     M461  ; CallLEDBuzzerFB正常完了2
        [note] フラグリセット
; CallLEDBuzzer送信エラー処理/RW2
3278  LD      M462  ; CallLEDBuzzerFB異常完了2
      OR      M463  ; CallLEDBuzzerFB機器異常完了2
      RST     M450  ; CallLEDBuzzerFB開始2
        [note] FB動作停止
      RST     M462  ; CallLEDBuzzerFB異常完了2
        [note] フラグリセット
      RST     M463  ; CallLEDBuzzerFB機器異常完了2
        [note] フラグリセット
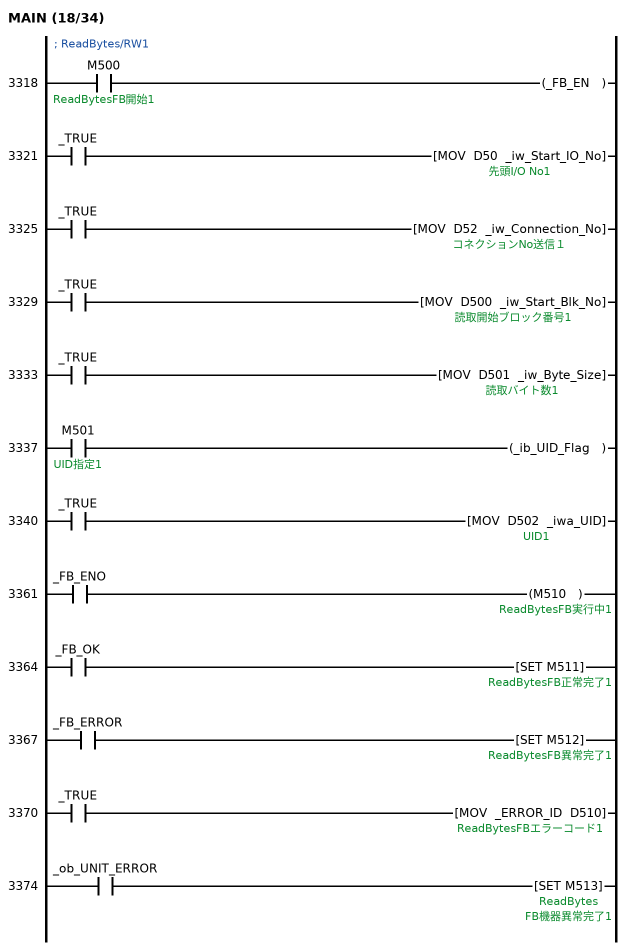
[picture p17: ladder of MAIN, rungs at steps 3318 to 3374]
; FB BLK START P+TAKAYA-TR3-E_ReadBytes(ReadBytes_1)
; ReadBytes/RW1
3318  LD      M500  ; ReadBytesFB開始1
      OUT     _FB_EN
3321  LD      _TRUE
      MOV     D50 _iw_Start_IO_No
3325  LD      _TRUE
      MOV     D52 _iw_Connection_No
3329  LD      _TRUE
      MOV     D500 _iw_Start_Blk_No
3333  LD      _TRUE
      MOV     D501 _iw_Byte_Size
3337  LD      M501  ; UID指定1
      OUT     _ib_UID_Flag
3340  LD      _TRUE
      MOV     D502 _iwa_UID  ; UID1
; FB START
; FB_NAME P+TAKAYA-TR3-E_ReadBytes
; INSTANCE_NAME ReadBytes_1
; FB IN_B:FB_EN
; FB OUT_FB_ENO:B
; FB IN_W:iw_Start_IO_No
; FB OUT_FB_OK:B
; FB IN_W:iw_Connection_No
; FB OUT_FB_ERROR:B
; FB IN_W:iw_Start_Blk_No
; FB OUT_ERROR_ID:W
; FB IN_W:iw_Byte_Size
; FB OUT_ob_UNIT_ERROR:B
; FB IN_B:ib_UID_Flag
; FB OUT_ow_UNIT_ERR_CODE:W
; FB IN_W:iwa_UID
; FB END
3361  LD      _FB_ENO
      OUT     M510  ; ReadBytesFB実行中1
3364  LD      _FB_OK
      SET     M511  ; ReadBytesFB正常完了1
3367  LD      _FB_ERROR
      SET     M512  ; ReadBytesFB異常完了1
3370  LD      _TRUE
      MOV     _ERROR_ID D510  ; ReadBytesFBエラーコード1
3374  LD      _ob_UNIT_ERROR
      SET     M513  ; ReadBytesFB機器異常完了1
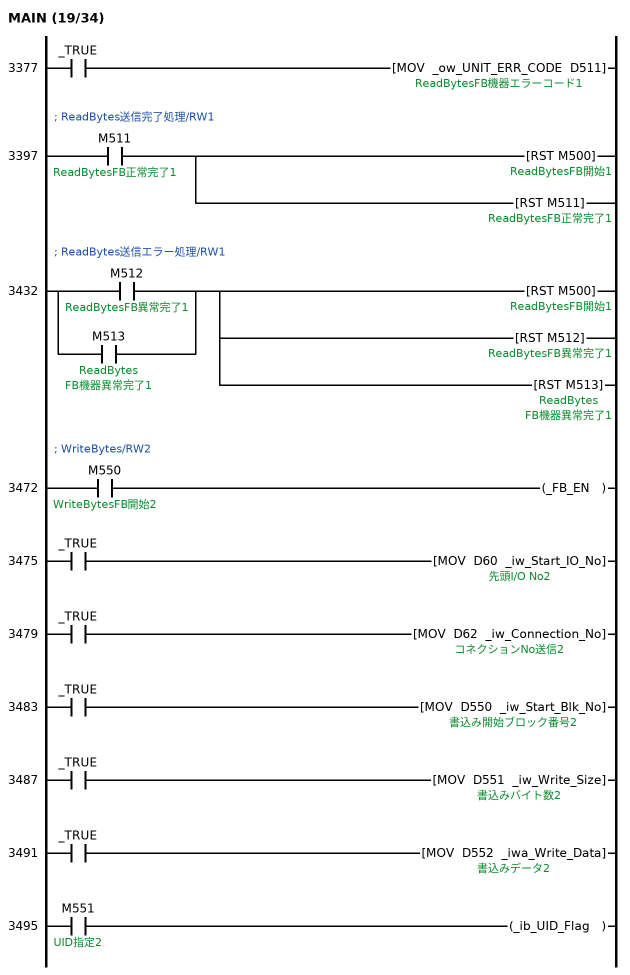
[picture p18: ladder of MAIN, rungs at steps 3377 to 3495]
3377  LD      _TRUE
      MOV     _ow_UNIT_ERR_CODE D511  ; ReadBytesFB機器エラーコード1
; FB BLK END
; ReadBytes送信完了処理/RW1
3397  LD      M511  ; ReadBytesFB正常完了1
      RST     M500  ; ReadBytesFB開始1
        [note] FB動作停止
      RST     M511  ; ReadBytesFB正常完了1
        [note] フラグリセット
; ReadBytes送信エラー処理/RW1
3432  LD      M512  ; ReadBytesFB異常完了1
      OR      M513  ; ReadBytesFB機器異常完了1
      RST     M500  ; ReadBytesFB開始1
        [note] FB動作停止
      RST     M512  ; ReadBytesFB異常完了1
        [note] フラグリセット
      RST     M513  ; ReadBytesFB機器異常完了1
        [note] フラグリセット
; FB BLK START P+TAKAYA-TR3-E_WriteBytes(WriteBytes_1)
; WriteBytes/RW2
3472  LD      M550  ; WriteBytesFB開始2
      OUT     _FB_EN
3475  LD      _TRUE
      MOV     D60 _iw_Start_IO_No
3479  LD      _TRUE
      MOV     D62 _iw_Connection_No
3483  LD      _TRUE
      MOV     D550 _iw_Start_Blk_No
3487  LD      _TRUE
      MOV     D551 _iw_Write_Size
3491  LD      _TRUE
      MOV     D552 _iwa_Write_Data  ; 書込みデータ2
3495  LD      M551  ; UID指定2
      OUT     _ib_UID_Flag
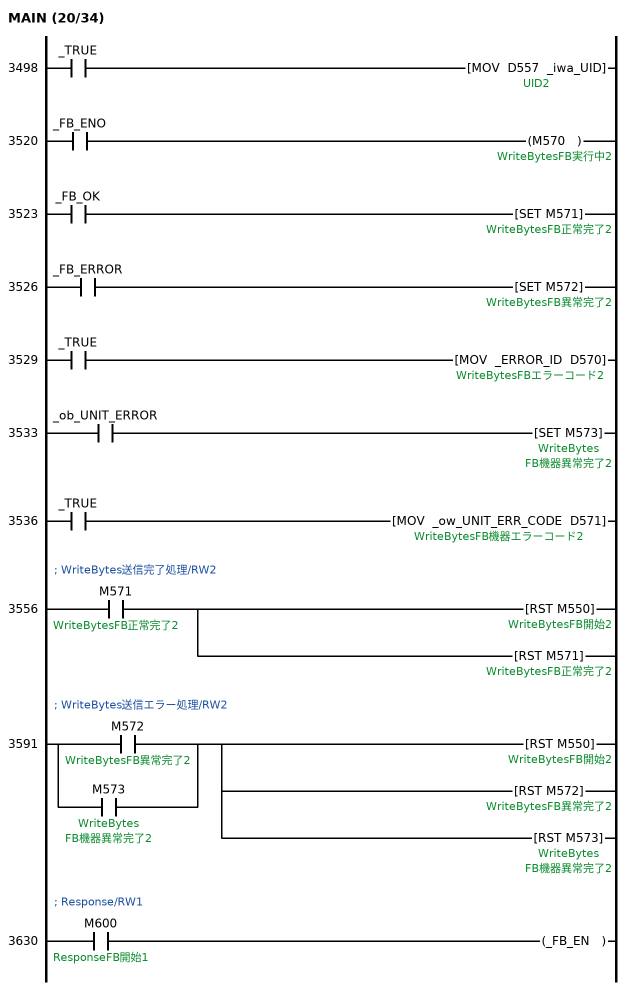
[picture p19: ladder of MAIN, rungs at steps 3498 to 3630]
3498  LD      _TRUE
      MOV     D557 _iwa_UID  ; UID2
; FB START
; FB_NAME P+TAKAYA-TR3-E_WriteBytes
; INSTANCE_NAME WriteBytes_1
; FB IN_B:FB_EN
; FB OUT_FB_ENO:B
; FB IN_W:iw_Start_IO_No
; FB OUT_FB_OK:B
; FB IN_W:iw_Connection_No
; FB OUT_FB_ERROR:B
; FB IN_W:iw_Start_Blk_No
; FB OUT_ERROR_ID:W
; FB IN_W:iw_Write_Size
; FB OUT_ob_UNIT_ERROR:B
; FB IN_W:iwa_Write_Data
; FB OUT_ow_UNIT_ERR_CODE:W
; FB IN_B:ib_UID_Flag
; FB IN_W:iwa_UID
; FB END
3520  LD      _FB_ENO
      OUT     M570  ; WriteBytesFB実行中2
3523  LD      _FB_OK
      SET     M571  ; WriteBytesFB正常完了2
3526  LD      _FB_ERROR
      SET     M572  ; WriteBytesFB異常完了2
3529  LD      _TRUE
      MOV     _ERROR_ID D570  ; WriteBytesFBエラーコード2
3533  LD      _ob_UNIT_ERROR
      SET     M573  ; WriteBytesFB機器異常完了2
3536  LD      _TRUE
      MOV     _ow_UNIT_ERR_CODE D571  ; WriteBytesFB機器エラーコード2
; FB BLK END
; WriteBytes送信完了処理/RW2
3556  LD      M571  ; WriteBytesFB正常完了2
      RST     M550  ; WriteBytesFB開始2
        [note] FB動作停止
      RST     M571  ; WriteBytesFB正常完了2
        [note] フラグリセット
; WriteBytes送信エラー処理/RW2
3591  LD      M572  ; WriteBytesFB異常完了2
      OR      M573  ; WriteBytesFB機器異常完了2
      RST     M550  ; WriteBytesFB開始2
        [note] FB動作停止
      RST     M572  ; WriteBytesFB異常完了2
        [note] フラグリセット
      RST     M573  ; WriteBytesFB機器異常完了2
        [note] フラグリセット
; FB BLK START P+TAKAYA-TR3-E_Response(Response_1)
; Response/RW1
3630  LD      M600  ; ResponseFB開始1
      OUT     _FB_EN
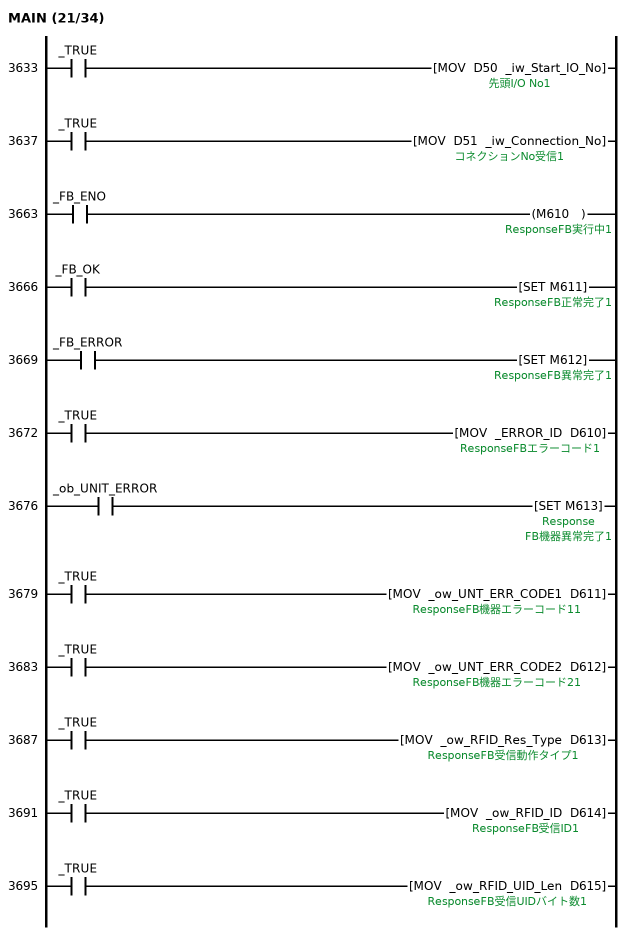
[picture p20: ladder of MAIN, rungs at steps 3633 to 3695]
3633  LD      _TRUE
      MOV     D50 _iw_Start_IO_No
3637  LD      _TRUE
      MOV     D51 _iw_Connection_No
; FB START
; FB_NAME P+TAKAYA-TR3-E_Response
; INSTANCE_NAME Response_1
; FB IN_B:FB_EN
; FB OUT_FB_ENO:B
; FB IN_W:iw_Start_IO_No
; FB OUT_FB_OK:B
; FB IN_W:iw_Connection_No
; FB OUT_FB_ERROR:B
; FB OUT_ERROR_ID:W
; FB OUT_ob_UNIT_ERROR:B
; FB OUT_ow_UNT_ERR_CODE1:W
; FB OUT_ow_UNT_ERR_CODE2:W
; FB OUT_ow_RFID_Res_Type:W
; FB OUT_ow_RFID_ID:W
; FB OUT_ow_RFID_UID_Len:W
; FB OUT_ow_RFID_Data_Len:W
; FB OUT_ow_RFID_UII_Len:W
; FB OUT_owa_RFID_UID:W
; FB OUT_owa_RFID_Data:W
; FB OUT_owa_RFID_UII:W
; FB END
3663  LD      _FB_ENO
      OUT     M610  ; ResponseFB実行中1
3666  LD      _FB_OK
      SET     M611  ; ResponseFB正常完了1
3669  LD      _FB_ERROR
      SET     M612  ; ResponseFB異常完了1
3672  LD      _TRUE
      MOV     _ERROR_ID D610  ; ResponseFBエラーコード1
3676  LD      _ob_UNIT_ERROR
      SET     M613  ; ResponseFB機器異常完了1
3679  LD      _TRUE
      MOV     _ow_UNT_ERR_CODE1 D611  ; ResponseFB機器エラーコード11
3683  LD      _TRUE
      MOV     _ow_UNT_ERR_CODE2 D612  ; ResponseFB機器エラーコード21
3687  LD      _TRUE
      MOV     _ow_RFID_Res_Type D613  ; ResponseFB受信動作タイプ1
3691  LD      _TRUE
      MOV     _ow_RFID_ID D614  ; ResponseFB受信ID1
3695  LD      _TRUE
      MOV     _ow_RFID_UID_Len D615  ; ResponseFB受信UIDバイト数1
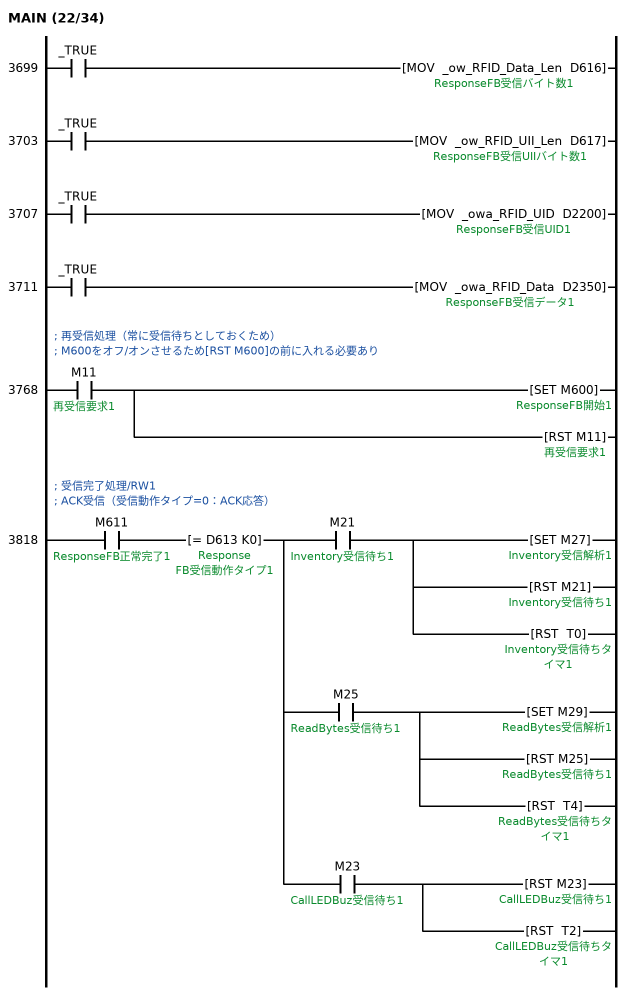
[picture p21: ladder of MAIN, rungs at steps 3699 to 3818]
3699  LD      _TRUE
      MOV     _ow_RFID_Data_Len D616  ; ResponseFB受信バイト数1
3703  LD      _TRUE
      MOV     _ow_RFID_UII_Len D617  ; ResponseFB受信UIIバイト数1
3707  LD      _TRUE
      MOV     _owa_RFID_UID D2200  ; ResponseFB受信UID1
3711  LD      _TRUE
      MOV     _owa_RFID_Data D2350  ; ResponseFB受信データ1
; FB BLK END
; 再受信処理（常に受信待ちとしておくため）
; M600をオフ/オンさせるため[RST M600]の前に入れる必要あり
3768  LD      M11  ; 再受信要求1
      SET     M600  ; ResponseFB開始1
        [note] 受信処理開始
      RST     M11  ; 再受信要求1
        [note] フラグリセット
; 受信完了処理/RW1
; ACK受信（受信動作タイプ=0：ACK応答）
3818  LD      M611  ; ResponseFB正常完了1
      AND=    D613 K0  ; ResponseFB受信動作タイプ1
      MPS
      AND     M21  ; Inventory受信待ち1
      SET     M27  ; Inventory受信解析1
        [note] Inventory受信解析：セット
      RST     M21  ; Inventory受信待ち1
        [note] フラグリセット
      RST     T0  ; Inventory受信待ちタイマ1
        [note] 正常処理のためタイマリセット
      MRD
      AND     M25  ; ReadBytes受信待ち1
      SET     M29  ; ReadBytes受信解析1
        [note] ReadBytes受信解析：セット
      RST     M25  ; ReadBytes受信待ち1
        [note] フラグリセット
      RST     T4  ; ReadBytes受信待ちタイマ1
        [note] 正常処理のためタイマリセット
      MPP
      AND     M23  ; CallLEDBuz受信待ち1
      RST     M23  ; CallLEDBuz受信待ち1
        [note] フラグリセット
      RST     T2  ; CallLEDBuz受信待ちタイマ1
        [note] 正常処理のためタイマリセット
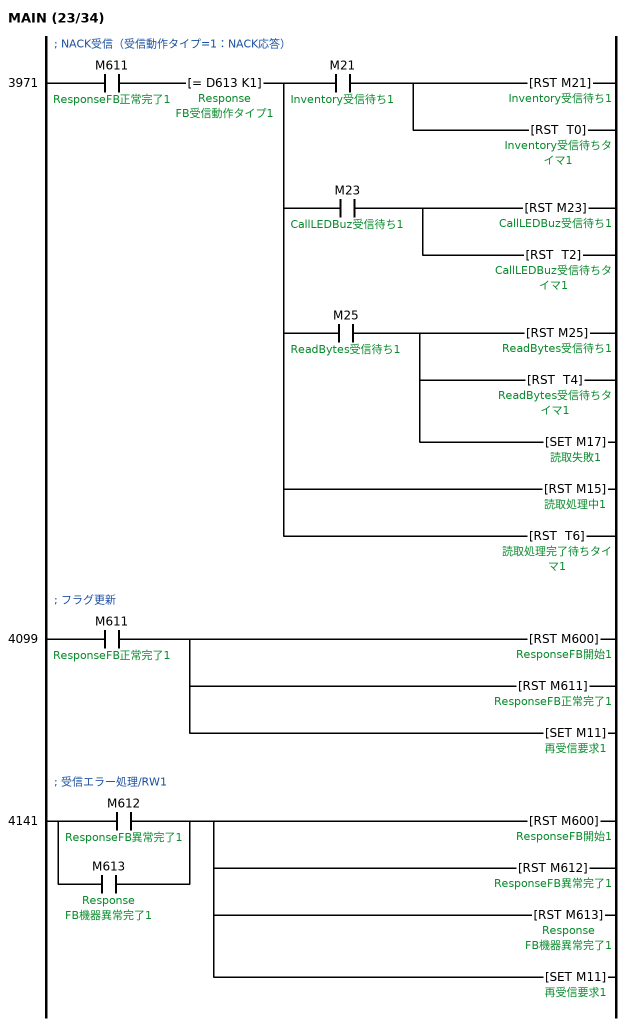
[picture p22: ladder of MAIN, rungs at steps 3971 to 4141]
; NACK受信（受信動作タイプ=1：NACK応答）
3971  LD      M611  ; ResponseFB正常完了1
      AND=    D613 K1  ; ResponseFB受信動作タイプ1
      MPS
      AND     M21  ; Inventory受信待ち1
      RST     M21  ; Inventory受信待ち1
        [note] フラグリセット
      RST     T0  ; Inventory受信待ちタイマ1
        [note] 正常処理のためタイマリセット
      MRD
      AND     M23  ; CallLEDBuz受信待ち1
      RST     M23  ; CallLEDBuz受信待ち1
        [note] フラグリセット
      RST     T2  ; CallLEDBuz受信待ちタイマ1
        [note] タイマリセット
      MRD
      AND     M25  ; ReadBytes受信待ち1
      RST     M25  ; ReadBytes受信待ち1
        [note] フラグリセット
      RST     T4  ; ReadBytes受信待ちタイマ1
        [note] タイマリセット
      SET     M17  ; 読取失敗1
        [note] 読取失敗：セット
      MPP
      RST     M15  ; 読取処理中1
        [note] フラグリセット
      RST     T6  ; 読取処理完了待ちタイマ1
        [note] タイマリセット
; フラグ更新
4099  LD      M611  ; ResponseFB正常完了1
      RST     M600  ; ResponseFB開始1
        [note] FB動作停止
      RST     M611  ; ResponseFB正常完了1
        [note] フラグリセット
      SET     M11  ; 再受信要求1
        [note] 再受信要求：セット
; 受信エラー処理/RW1
4141  LD      M612  ; ResponseFB異常完了1
      OR      M613  ; ResponseFB機器異常完了1
      RST     M600  ; ResponseFB開始1
        [note] FB動作停止
      RST     M612  ; ResponseFB異常完了1
        [note] フラグリセット
      RST     M613  ; ResponseFB機器異常完了1
        [note] フラグリセット
      SET     M11  ; 再受信要求1
        [note] 再受信要求：セット
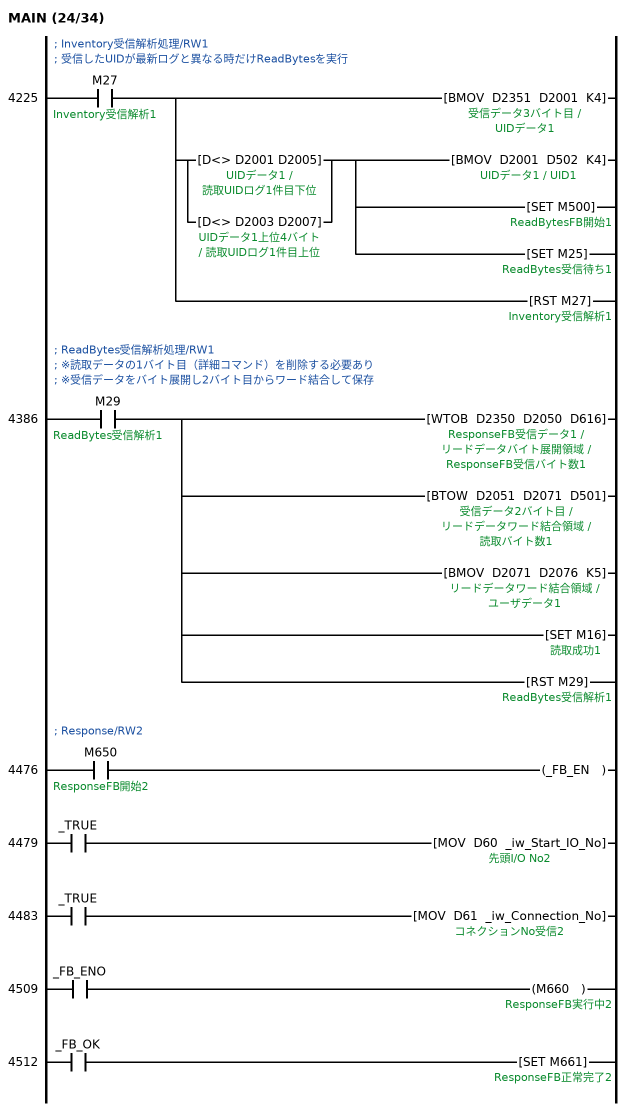
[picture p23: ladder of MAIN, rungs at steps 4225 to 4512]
; Inventory受信解析処理/RW1
; 受信したUIDが最新ログと異なる時だけReadBytesを実行
4225  LD      M27  ; Inventory受信解析1
      BMOV    D2351 D2001 K4  ; 受信データ3バイト目 / UIDデータ1
        [note] UIDデータを保存（3バイト目から）
      MPS
      LDD<>   D2001 D2005  ; UIDデータ1 / 読取UIDログ1件目下位
      ORD<>   D2003 D2007  ; UIDデータ1上位4バイト / 読取UIDログ1件目上位
      ANB
      BMOV    D2001 D502 K4
        [note] 指定UIDを設定
      SET     M500  ; ReadBytesFB開始1
        [note] ReadBytes実行
      SET     M25  ; ReadBytes受信待ち1
        [note] ReadBytes受信待ちフラグ：セット
      MPP
      RST     M27  ; Inventory受信解析1
        [note] フラグリセット
; ReadBytes受信解析処理/RW1
; ※読取データの1バイト目（詳細コマンド）を削除する必要あり
; ※受信データをバイト展開し2バイト目からワード結合して保存
4386  LD      M29  ; ReadBytes受信解析1
      WTOB    D2350 D2050 D616  ; リードデータバイト展開領域
        [note] 受信データをバイト展開
      BTOW    D2051 D2071 D501  ; 受信データ2バイト目 / リードデータワード結合領域
        [note] 2バイト目から再度ワード結合
      BMOV    D2071 D2076 K5  ; ユーザデータ1
        [note] 読取データを保存（5ワード固定）
      SET     M16  ; 読取成功1
        [note] 読取成功：セット
      RST     M29  ; ReadBytes受信解析1
        [note] フラグリセット
; FB BLK START P+TAKAYA-TR3-E_Response(Response_2)
; Response/RW2
4476  LD      M650  ; ResponseFB開始2
      OUT     _FB_EN
4479  LD      _TRUE
      MOV     D60 _iw_Start_IO_No
4483  LD      _TRUE
      MOV     D61 _iw_Connection_No
; FB START
; FB_NAME P+TAKAYA-TR3-E_Response
; INSTANCE_NAME Response_2
; FB IN_B:FB_EN
; FB OUT_FB_ENO:B
; FB IN_W:iw_Start_IO_No
; FB OUT_FB_OK:B
; FB IN_W:iw_Connection_No
; FB OUT_FB_ERROR:B
; FB OUT_ERROR_ID:W
; FB OUT_ob_UNIT_ERROR:B
; FB OUT_ow_UNT_ERR_CODE1:W
; FB OUT_ow_UNT_ERR_CODE2:W
; FB OUT_ow_RFID_Res_Type:W
; FB OUT_ow_RFID_ID:W
; FB OUT_ow_RFID_UID_Len:W
; FB OUT_ow_RFID_Data_Len:W
; FB OUT_ow_RFID_UII_Len:W
; FB OUT_owa_RFID_UID:W
; FB OUT_owa_RFID_Data:W
; FB OUT_owa_RFID_UII:W
; FB END
4509  LD      _FB_ENO
      OUT     M660  ; ResponseFB実行中2
4512  LD      _FB_OK
      SET     M661  ; ResponseFB正常完了2
4515  LD      _FB_ERROR
      SET     M662  ; ResponseFB異常完了2
4518  LD      _TRUE
      MOV     _ERROR_ID D660  ; ResponseFBエラーコード2
4522  LD      _ob_UNIT_ERROR
      SET     M663  ; ResponseFB機器異常完了2
4525  LD      _TRUE
      MOV     _ow_UNT_ERR_CODE1 D661  ; ResponseFB機器エラーコード12
4529  LD      _TRUE
      MOV     _ow_UNT_ERR_CODE2 D662  ; ResponseFB機器エラーコード22
4533  LD      _TRUE
      MOV     _ow_RFID_Res_Type D663  ; ResponseFB受信動作タイプ2
4537  LD      _TRUE
      MOV     _ow_RFID_ID D664  ; ResponseFB受信ID2
4541  LD      _TRUE
      MOV     _ow_RFID_UID_Len D665  ; ResponseFB受信UIDバイト数2
4545  LD      _TRUE
      MOV     _ow_RFID_Data_Len D666  ; ResponseFB受信バイト数2
4549  LD      _TRUE
      MOV     _ow_RFID_UII_Len D667  ; ResponseFB受信UIIバイト数2
4553  LD      _TRUE
      MOV     _owa_RFID_UID D2500  ; ResponseFB受信UID2
4557  LD      _TRUE
      MOV     _owa_RFID_Data D2650  ; ResponseFB受信データ2
; FB BLK END
; 再受信処理（常に受信待ちとしておくため）
; M650をオフ/オンさせるため[RST M650]の前に入れる必要あり
4614  LD      M12  ; 再受信要求2
      SET     M650  ; ResponseFB開始2
        [note] 受信処理開始
      RST     M12  ; 再受信要求2
        [note] フラグリセット
; 受信完了処理/RW2
; ACK受信（受信動作タイプ=0：ACK応答）
4664  LD      M661  ; ResponseFB正常完了2
      AND=    D663 K0  ; ResponseFB受信動作タイプ2
      MPS
      AND     M22  ; Inventory受信待ち2
      SET     M28  ; Inventory受信解析2
        [note] Inventory受信解析：セット
      RST     M22  ; Inventory受信待ち2
        [note] フラグリセット
      RST     T1  ; Inventory受信待ちタイマ2
        [note] 正常処理のためタイマリセット
      MRD
      AND     M26  ; WriteBytes受信待ち2
      SET     M30  ; WriteBytes受信解析2
        [note] WriteBytes受信解析：セット
      RST     M26  ; WriteBytes受信待ち2
        [note] フラグリセット
      RST     T5  ; WriteBytes受信待ちタイマ2
        [note] 正常処理のためタイマリセット
      MPP
      AND     M24  ; CallLEDBuz受信待ち2
      RST     M24  ; CallLEDBuz受信待ち2
        [note] フラグリセット
      RST     T3  ; CallLEDBuz受信待ちタイマ2
        [note] 正常処理のためタイマリセット
; NACK受信（受信動作タイプ=1：NACK応答）
4817  LD      M661  ; ResponseFB正常完了2
      AND=    D663 K1  ; ResponseFB受信動作タイプ2
      MPS
      AND     M22  ; Inventory受信待ち2
      RST     M22  ; Inventory受信待ち2
        [note] フラグリセット
      RST     T1  ; Inventory受信待ちタイマ2
        [note] 正常処理のためタイマリセット
      MRD
      AND     M24  ; CallLEDBuz受信待ち2
      RST     M24  ; CallLEDBuz受信待ち2
        [note] フラグリセット
      RST     T3  ; CallLEDBuz受信待ちタイマ2
        [note] タイマリセット
      MRD
      AND     M26  ; WriteBytes受信待ち2
      RST     M26  ; WriteBytes受信待ち2
        [note] フラグリセット
      RST     T5  ; WriteBytes受信待ちタイマ2
        [note] タイマリセット
      SET     M20  ; 書込失敗2
        [note] 書込失敗：セット
      MPP
      RST     M18  ; 書込処理中2
        [note] フラグリセット
      RST     T7  ; 書込処理完了待ちタイマ2
        [note] タイマリセット
; フラグ更新
4945  LD      M661  ; ResponseFB正常完了2
      RST     M650  ; ResponseFB開始2
        [note] FB動作停止
      RST     M661  ; ResponseFB正常完了2
        [note] フラグリセット
      SET     M12  ; 再受信要求2
        [note] 再受信要求：セット
; 受信エラー処理/RW2
4987  LD      M662  ; ResponseFB異常完了2
      OR      M663  ; ResponseFB機器異常完了2
      RST     M650  ; ResponseFB開始2
        [note] FB動作停止
      RST     M662  ; ResponseFB異常完了2
        [note] フラグリセット
      RST     M663  ; ResponseFB機器異常完了2
        [note] フラグリセット
      SET     M12  ; 再受信要求2
        [note] 再受信要求：セット
; Inventory受信解析処理/RW2
; 受信したUIDが最新ログと異なる時だけWriteBytesを実行
; ※書込みデータはPLCの時刻情報の内月日時分秒の10桁数値
; ※各2桁数値の上位が0の場合ASCIIコードの0をセットする
5129  LD      M28  ; Inventory受信解析2
      BMOV    D2651 D2025 K4  ; 受信データ3バイト目 / UIDデータ2
        [note] UIDデータを保存（3バイト目から）
      MPS
      LDD<>   D2025 D2029  ; UIDデータ2 / 書込UIDログ1件目下位
      ORD<>   D2027 D2031  ; UIDデータ2上位4バイト / 書込UIDログ1件目上位
      ANB
      BMOV    D2025 D557 K4
        [note] 指定UIDを設定
      DATERD  D12  ; 日時データ
        [note] PLCの日時データ取得
      BINDA   D13 D2136  ; 月 / ライトデータASCII変換領域
        [note] 月データをASCII変換
      MOV     D2138 D552  ; 下2桁
        [note] 月データを1ワード目にコピー
      MPS
      AND<    D13 K10  ; 月
      +       K16 D552
        [note] 月が1桁の場合上位を20hから30hへ
      MPP
      BINDA   D14 D2136  ; 日
        [note] 日データをASCII変換
      MOV     D2138 D553  ; 書込みデータ2ワード目
        [note] 日データを2ワード目にコピー
      MPS
      AND<    D14 K10  ; 日
      +       K16 D553
        [note] 月が1桁の場合上位を20hから30hへ
      MPP
      BINDA   D15 D2136  ; 時
        [note] 時データをASCII変換
      MOV     D2138 D554  ; 書込みデータ3ワード目
        [note] 時データを3ワード目にコピー
      MPS
      AND<    D15 K10  ; 時
      +       K16 D554
        [note] 月が1桁の場合上位を20hから30hへ
      MPP
      BINDA   D16 D2136  ; 分
        [note] 分データをASCII変換
      MOV     D2138 D555  ; 書込みデータ4ワード目
        [note] 分データを4ワード目にコピー
      MPS
      AND<    D16 K10  ; 分
      +       K16 D555
        [note] 月が1桁の場合上位を20hから30hへ
      MPP
      BINDA   D17 D2136  ; 秒
        [note] 秒データをASCII変換
      MOV     D2138 D556  ; 書込みデータ5ワード目
        [note] 秒データを5ワード目にコピー
      MPS
      AND<    D17 K10  ; 秒
      +       K16 D556
        [note] 月が1桁の場合上位を20hから30hへ
      MPP
      SET     M550  ; WriteBytesFB開始2
        [note] WriteBytes実行
      SET     M26  ; WriteBytes受信待ち2
        [note] WriteBytes受信待ちフラグ：セット
      MPP
      RST     M28  ; Inventory受信解析2
        [note] フラグリセット
; WriteBytes受信解析処理/RW2
5537  LD      M30  ; WriteBytes受信解析2
      BMOV    D552 D2106 K5  ; ユーザデータ2
        [note] 書込データを保存（5ワード固定）
      SET     M19  ; 書込成功2
        [note] 書込成功：セット
      RST     M30  ; WriteBytes受信解析2
        [note] フラグリセット
; 読取成功/RW1
5589  LD      M16  ; 読取成功1
      RST     M16  ; 読取成功1
        [note] フラグリセット
      RST     M15  ; 読取処理中1
        [note] フラグリセット
      RST     T6  ; 読取処理完了待ちタイマ1
        [note] タイマリセット
      INC     D1000  ; 読取回数
        [note] 読取回数+1
      BMOV    D2001 D2005 K20
        [note] 読取UIDログを更新
      BMOV    D2076 D2081 K25  ; 読取ユーザデータログ1件目
        [note] 読取ユーザデータログを更新
      SET     M31  ; GOT表示1
        [note] GOT表示：セット
      MOV     K1 D400
        [note] LED制御ポート=1/青点灯
      MOV     K0 D403
        [note] ブザー音：0/ピー
      SET     M400  ; CallLEDBuzzerFB開始1
        [note] CallLEDBuzzer実行
      SET     M23  ; CallLEDBuz受信待ち1
        [note] 受信待ちフラグセット
; 読取失敗/RW2
5737  LD      M17  ; 読取失敗1
      RST     M17  ; 読取失敗1
        [note] フラグリセット
      MOV     K4 D400
        [note] LED制御ポート=4/赤点灯
      MOV     K1 D403
        [note] ブザー音：1/ピッピッピ
      SET     M400  ; CallLEDBuzzerFB開始1
        [note] CallLEDBuzzer実行
      SET     M23  ; CallLEDBuz受信待ち1
        [note] 受信待ちフラグセット
; 書込成功/RW2
5811  LD      M19  ; 書込成功2
      RST     M19  ; 書込成功2
        [note] フラグリセット
      RST     M18  ; 書込処理中2
        [note] フラグリセット
      RST     T7  ; 書込処理完了待ちタイマ2
        [note] タイマリセット
      INC     D1001  ; 書込回数
        [note] 書込回数+1
      BMOV    D2025 D2029 K20
        [note] 書込UIDログを更新
      BMOV    D2106 D2111 K25  ; 書込ユーザデータログ1件目
        [note] 書込ユーザデータログを更新
      SET     M32  ; GOT表示2
        [note] GOT表示：セット
      MOV     K1 D450
        [note] LED制御ポート=1/青点灯
      MOV     K0 D453
        [note] ブザー音：0/ピー
      SET     M450  ; CallLEDBuzzerFB開始2
        [note] CallLEDBuzzer実行
      SET     M24  ; CallLEDBuz受信待ち2
        [note] 受信待ちフラグセット
5951  LD      M20  ; 書込失敗2
      RST     M20  ; 書込失敗2
        [note] フラグリセット
      MOV     K4 D450
        [note] LED制御ポート=4/赤点灯
      MOV     K1 D453
        [note] ブザー音：1/ピッピッピ
      SET     M450  ; CallLEDBuzzerFB開始2
        [note] CallLEDBuzzer実行
      SET     M24  ; CallLEDBuz受信待ち2
        [note] 受信待ちフラグセット
; GOT表示/RW1
6025  LD      M31  ; GOT表示1
      MPS
      AND>    D1000 K0  ; 読取回数
      ?OP5903 D2007 D1021  ; 読取UID表示1件目上位
        [note] UID表示/読取1件目上位4バイト
      ?OP5903 D2005 D1025  ; 読取UID表示1件目下位
        [note] UID表示/読取1件目下位4バイト
      BMOV    D2081 D1121 K5  ; 読取ユーザデータ表示1件目
        [note] ユーザデータ表示/読取1件目
      MRD
      AND>    D1000 K1  ; 読取回数
      ?OP5903 D2011 D1031  ; 読取UIDログ2件目上位 / 読取UID表示2件目上位
        [note] UID表示/読取2件目上位4バイト
      ?OP5903 D2009 D1035  ; 読取UIDログ2件目下位 / 読取UID表示2件目下位
        [note] UID表示/読取2件目下位4バイト
      BMOV    D2086 D1131 K5  ; 読取ユーザデータログ2件目 / 読取ユーザデータ表示2件目
        [note] ユーザデータ表示/読取2件目
      MRD
      AND>    D1000 K2  ; 読取回数
      ?OP5903 D2015 D1041  ; 読取UIDログ3件目上位 / 読取UID表示3件目上位
        [note] UID表示/読取3件目上位4バイト
      ?OP5903 D2013 D1045  ; 読取UIDログ3件目下位 / 読取UID表示3件目下位
        [note] UID表示/読取3件目下位4バイト
      BMOV    D2091 D1141 K5  ; 読取ユーザデータログ3件目 / 読取ユーザデータ表示3件目
        [note] ユーザデータ表示/読取3件目
      MRD
      AND>    D1000 K3  ; 読取回数
      ?OP5903 D2019 D1051  ; 読取UIDログ4件目上位 / 読取UID表示4件目上位
        [note] UID表示/読取4件目上位4バイト
      ?OP5903 D2017 D1055  ; 読取UIDログ4件目下位 / 読取UID表示4件目下位
        [note] UID表示/読取4件目下位4バイト
      BMOV    D2096 D1151 K5  ; 読取ユーザデータログ4件目 / 読取ユーザデータ表示4件目
        [note] ユーザデータ表示/読取4件目
      MRD
      AND>    D1000 K4  ; 読取回数
      ?OP5903 D2023 D1061  ; 読取UIDログ5件目上位 / 読取UID表示5件目上位
        [note] UID表示/読取5件目上位4バイト
      ?OP5903 D2021 D1065  ; 読取UIDログ5件目下位 / 読取UID表示5件目下位
        [note] UID表示/読取5件目下位4バイト
      BMOV    D2101 D1161 K5  ; 読取ユーザデータログ5件目 / 読取ユーザデータ表示5件目
        [note] ユーザデータ表示/読取5件目
      MPP
      RST     M31  ; GOT表示1
; GOT表示/RW2
6341  LD      M32  ; GOT表示2
      MPS
      AND>    D1001 K0  ; 書込回数
      ?OP5903 D2031 D1071  ; 書込UID表示1件目上位
        [note] UID表示/読取1件目上位4バイト
      ?OP5903 D2029 D1075  ; 書込UID表示1件目下位
        [note] UID表示/読取1件目下位4バイト
      BMOV    D2111 D1171 K5  ; 書込ユーザデータ表示1件目
        [note] ユーザデータ表示/読取1件目
      MRD
      AND>    D1001 K1  ; 書込回数
      ?OP5903 D2035 D1081  ; 書込UIDログ2件目上位 / 書込UID表示2件目上位
        [note] UID表示/読取2件目上位4バイト
      ?OP5903 D2033 D1085  ; 書込UIDログ2件目下位 / 書込UID表示2件目下位
        [note] UID表示/読取2件目下位4バイト
      BMOV    D2116 D1181 K5  ; 書込ユーザデータログ2件目 / 書込ユーザデータ表示2件目
        [note] ユーザデータ表示/読取2件目
      MRD
      AND>    D1001 K2  ; 書込回数
      ?OP5903 D2039 D1091  ; 書込UIDログ3件目上位 / 書込UID表示3件目上位
        [note] UID表示/読取3件目上位4バイト
      ?OP5903 D2037 D1095  ; 書込UIDログ3件目下位 / 書込UID表示3件目下位
        [note] UID表示/読取3件目下位4バイト
      BMOV    D2121 D1191 K5  ; 書込ユーザデータログ3件目 / 書込ユーザデータ表示3件目
        [note] ユーザデータ表示/読取3件目
      MRD
      AND>    D1001 K3  ; 書込回数
      ?OP5903 D2043 D1101  ; 書込UIDログ4件目上位 / 書込UID表示4件目上位
        [note] UID表示/読取4件目上位4バイト
      ?OP5903 D2041 D1105  ; 書込UIDログ4件目下位 / 書込UID表示4件目下位
        [note] UID表示/読取4件目下位4バイト
      BMOV    D2126 D1201 K5  ; 書込ユーザデータログ4件目 / 書込ユーザデータ表示4件目
        [note] ユーザデータ表示/読取4件目
      MRD
      AND>    D1001 K4  ; 書込回数
      ?OP5903 D2047 D1111  ; 書込UIDログ5件目上位 / 書込UID表示5件目上位
        [note] UID表示/読取5件目上位4バイト
      ?OP5903 D2045 D1115  ; 書込UIDログ5件目下位 / 書込UID表示5件目下位
        [note] UID表示/読取5件目下位4バイト
      BMOV    D2131 D1211 K5  ; 書込ユーザデータログ5件目 / 書込ユーザデータ表示5件目
        [note] ユーザデータ表示/読取5件目
      MPP
      RST     M32  ; GOT表示2
; GOT表示クリア
6658  LD      M1004  ; GOT表示クリア
      MOV     K0 D1000
        [note] 読取回数クリア
      MOV     K0 D1001
        [note] 書込回数クリア
      FMOV    K0 D1021 K100
        [note] UID表示クリア
      FMOV    K0 D1121 K100
        [note] データ表示クリア
; ステータス更新
6717  LD      M3  ; TCP/IP接続完了1
      SET     M1002  ; 接続状態1
6719  LDI     M3  ; TCP/IP接続完了1
      RST     M1002  ; 接続状態1
6721  LD      M4  ; TCP/IP接続完了2
      SET     M1003  ; 接続状態2
6723  LDI     M4  ; TCP/IP接続完了2
      RST     M1003  ; 接続状態2
6725  LDI     M3  ; TCP/IP接続完了1
      ANI     M4  ; TCP/IP接続完了2
      SET     Y10  ; 動作異常
      RST     Y11  ; 正常起動
      RST     M1000  ; 連続処理中
6730  LD      M3  ; TCP/IP接続完了1
      AND     M4  ; TCP/IP接続完了2
      RST     Y10  ; 動作異常
      SET     Y11  ; 正常起動
6734  LD      M3  ; TCP/IP接続完了1
      ANI     M4  ; TCP/IP接続完了2
      LDI     M3  ; TCP/IP接続完了1
      AND     M4  ; TCP/IP接続完了2
      ORB
      SET     Y10  ; 動作異常
      SET     Y11  ; 正常起動
6741  LD      M1000  ; 連続処理中
      SET     M1001  ; 処理状態
      SET     Y12  ; 処理継続中
6744  LDI     M1000  ; 連続処理中
      RST     M1001  ; 処理状態
      RST     Y12  ; 処理継続中
6747  END
END_PROGRAM

FUNCTION_BLOCK P+TAKAYA-TR3-E_CallLEDBuzzer  // LED&ブザーの制御
VAR_INPUT
  FB_EN : BOOL;  (* 実行命令 *)
  iw_Start_IO_No : INT;  (* 先頭I/ONo. *)
  iw_Connection_No : INT;  (* コネクションNo. *)
END_VAR
VAR_OUTPUT
  FB_OK : BOOL;  (* 正常完了 *)
  FB_ERROR : BOOL;  (* 異常完了フラグ *)
  ERROR_ID : INT;  (* エラーコード *)
  FB_ENO : BOOL;  (* 実行状態 *)
END_VAR
VAR
  vb_Program_Init : BOOL;  (* プログラム実行前初期化 *)
  vb_Check_Input : BOOL;  (* 入力範囲判定1 *)
  vb_Tmp_Error : BOOL;  (* エラー内部フラグ *)
  vb_Tmp_OK : BOOL;  (* FB完了内部フラグ *)
  vw_Start_IO_No_Tmp : INT;  (* 先頭I/ONo.内部 *)
  vw_Connection_No_Tmp : INT;  (* コネクションNo.内部 *)
  vb_Tmp_Unit_Error : BOOL;  (* 機器エラー内部フラグ *)
  vb_Program_End : BOOL;  (* FB終了処理内部フラグ *)
END_VAR
VAR_OUTPUT
  ob_UNIT_ERROR : BOOL;  (* 機器異常完了フラグ *)
  ow_UNIT_ERR_CODE : INT;  (* 機器エラーコード *)
END_VAR
VAR
  vwa_Control_Data : ARRAY [0..1] OF INT;  (* コントロールデータ *)
  vb_Sum_Calc : BOOL;  (* SUM計算開始フラグ *)
  vb_Send_Ready : BOOL;  (* 送信準備完了フラグ *)
  vwa_Send_Sum : ARRAY [0..1] OF INT;  (* 送信SUM合計値 *)
  vwa_Buff_Send_Byte : ARRAY [0..13] OF INT;  (* 送信バッファバイト *)
  vba_Send : ARRAY [0..2] OF BOOL;  (* 送信処理フラグ *)
  vb_UDE : BOOL;  (* QnUDE(H)認識フラグ *)
END_VAR
VAR_INPUT
  iw_Port_Type : INT;  (* 制御ポート *)
END_VAR
VAR
  vw_Port_Type_Tmp : INT;  (* LEDの選択内部 *)
END_VAR
VAR_INPUT
  iw_Mode : INT;  (* LEDの動作モード *)
  iw_Lighting_Time : INT;  (* LED点灯時間 *)
END_VAR
VAR
  vw_Mode_Tmp : INT;  (* LEDの動作モード内部 *)
  vw_Lighting_Time_Tmp : INT;  (* LED点灯時間内部 *)
END_VAR
VAR_INPUT
  iw_Buzzer_Type : INT;  (* ブザー音 *)
  iw_Ringing_Time : INT;  (* ブザー音鳴動時間 *)
END_VAR
VAR
  vw_Buzzer_Type_Tmp : INT;  (* ブザー音内部 *)
  vw_Ringing_Time_Tmp : INT;  (* ブザー音鳴動時間内部 *)
  vb_Check_Input2 : BOOL;  (* 入力範囲判定2 *)
  vb_Join_Byte : BOOL;  (* バイト単位結合 *)
  vwa_Buff_Send_Word : ARRAY [0..7] OF INT;  (* 送信バッファワード *)
  vw_ZTmp : INT;  (* インデックスレジスタ一時退避 *)
END_VAR
; ＊＊＊＊＊＊＊＊＊＊＊＊＊＊＊＊＊＊＊＊
; ＊FB名称:P+TAKAYA-TR3-E_CallLEDBuzzer
; ＊機能:LED&ブザーの制御
; ＊バージョン:Ver1.00A
; ＊＊＊＊＊＊＊＊＊＊＊＊＊＊＊＊＊＊＊＊
; FB非実行時接点OFF
103   LDI     FB_EN
      RST     vb_Program_Init
      RST     vb_Check_Input
      RST     vb_Check_Input2
      RST     vb_Join_Byte
      RST     vb_Sum_Calc
      RST     vb_Send_Ready
; FB実行開始時
125   LDP     FB_EN
      SET     FB_ENO
      SET     vb_Program_Init
; プログラム実行前初期化
145   LD      vb_Program_Init
      MOV     K0 ERROR_ID
      MOV     K0 ow_UNIT_ERR_CODE
      MOV     K0 vw_Port_Type_Tmp
      MOV     K0 vw_Mode_Tmp
      MOV     K0 vw_Lighting_Time_Tmp
      MOV     K0 vw_Buzzer_Type_Tmp
      MOV     K0 vw_Ringing_Time_Tmp
      FMOV    K0 vwa_Buff_Send_Byte[0] K14
      FMOV    K0 vwa_Buff_Send_Word[0] K8
      FMOV    K0 vwa_Control_Data[0] K2
      FMOV    K0 vwa_Send_Sum[0] K2
      SET     vb_Check_Input
      RST     vb_Program_Init
; 入力範囲判定
189   LD      vb_Check_Input
      MPS
      AND=    H0FFFF iw_Start_IO_No
      SET     vb_UDE
      MRD
      ANI     vb_UDE
      LD<     iw_Connection_No K2
      OR=     iw_Connection_No K9
      OR>     iw_Connection_No K16
      ANB
      SET     vb_Tmp_Error
      MOV     K100 ERROR_ID
      MRD
      AND     vb_UDE
      LD<     iw_Connection_No K1
      OR>     iw_Connection_No K16
      ANB
      SET     vb_Tmp_Error
      MOV     K100 ERROR_ID
      MRD
      LD<     iw_Port_Type K0
      OR=     iw_Port_Type K2
      OR=     iw_Port_Type K3
      OR>     iw_Port_Type K5
      ANB
      SET     vb_Tmp_Error
      MOV     K106 ERROR_ID
      MRD
      LD<     iw_Mode K0
      OR>     iw_Mode K2
      ANB
      SET     vb_Tmp_Error
      MOV     K104 ERROR_ID
      MRD
      ANI     vb_Tmp_Error
      MOV     iw_Connection_No vw_Connection_No_Tmp
      MOV     iw_Start_IO_No vw_Start_IO_No_Tmp
      MOV     iw_Port_Type vw_Port_Type_Tmp
      MOV     iw_Mode vw_Mode_Tmp
      SET     vb_Check_Input2
      MPP
      RST     vb_Check_Input
; 入力範囲2
281   LD      vb_Check_Input2
      MPS
      LD<>    iw_Mode K2
      LD<     iw_Lighting_Time K0
      OR>     iw_Lighting_Time K255
      ANB
      LD=     iw_Mode K2
      LD<     iw_Lighting_Time K0
      OR>     iw_Lighting_Time K1
      ANB
      ORB
      ANB
      SET     vb_Tmp_Error
      MOV     K105 ERROR_ID
      MRD
      LD<     iw_Buzzer_Type K0
      LD>     iw_Buzzer_Type K8
      AND<>   iw_Buzzer_Type K255
      ORB
      ANB
      SET     vb_Tmp_Error
      MOV     K107 ERROR_ID
      MRD
      LD<>    iw_Buzzer_Type K255
      LD<     iw_Ringing_Time K0
      OR>     iw_Ringing_Time K1
      ANB
      LD=     iw_Buzzer_Type K255
      LD<     iw_Ringing_Time K0
      OR>     iw_Ringing_Time K255
      ANB
      ORB
      ANB
      SET     vb_Tmp_Error
      MOV     K108 ERROR_ID
      MRD
      ANI     vb_Tmp_Error
      MOV     iw_Lighting_Time vw_Lighting_Time_Tmp
      MOV     iw_Buzzer_Type vw_Buzzer_Type_Tmp
      MOV     iw_Ringing_Time vw_Ringing_Time_Tmp
      SET     vba_Send[0]
      MPP
      RST     vb_Check_Input2
; インデックスレジスタ一時退避
383   LD      SM400
      MOV     Z9 vw_ZTmp
      MOV     K0 Z9
; インデックスレジスタ値格納
403   LD      FB_ENO
      MPS
      ANI     vb_UDE
      MOV     vw_Start_IO_No_Tmp Z9
      SFR     Z9 K4
      MPP
      AND     vb_UDE
      MOV     K0 Z9
; 送信フォーマット作成
431   LD      vba_Send[0]
      MOV     H2 vwa_Buff_Send_Byte[1]
      MOV     H0 vwa_Buff_Send_Byte[2]
      MOV     H4E vwa_Buff_Send_Byte[3]
      MOV     H6 vwa_Buff_Send_Byte[4]
      MOV     H57 vwa_Buff_Send_Byte[5]
      MOV     vw_Port_Type_Tmp vwa_Buff_Send_Byte[6]
      MOV     vw_Mode_Tmp vwa_Buff_Send_Byte[7]
      MOV     vw_Lighting_Time_Tmp vwa_Buff_Send_Byte[8]
      MOV     vw_Buzzer_Type_Tmp vwa_Buff_Send_Byte[9]
      MOV     vw_Ringing_Time_Tmp vwa_Buff_Send_Byte[10]
      MOV     H3 vwa_Buff_Send_Byte[11]
      MOV     H0D vwa_Buff_Send_Byte[13]
      SET     vb_Sum_Calc
      RST     vba_Send[0]
; SUMの計算
468   LD      vb_Sum_Calc
      WSUM    vwa_Buff_Send_Byte[1] vwa_Send_Sum[0] K11
      DAND    H0FF vwa_Send_Sum[0]
      MOV     vwa_Send_Sum[0] vwa_Buff_Send_Byte[12]
      SET     vb_Join_Byte
      RST     vb_Sum_Calc
; バイト単位データ結合
496   LD      vb_Join_Byte
      BTOW    vwa_Buff_Send_Byte[1] vwa_Buff_Send_Word[1] K13
      MOV     K13 vwa_Buff_Send_Word[0]
      SET     vb_Send_Ready
      RST     vb_Join_Byte
; 送信処理
514   LD      vb_Send_Ready
      MPS
      ANI     vb_UDE
      ZP.BUFSND "U0Z9" vw_Connection_No_Tmp vwa_Control_Data[0] vwa_Buff_Send_Word[0] vba_Send[1]
      MPP
      AND     vb_UDE
      SP.SOCSND "U0" vw_Connection_No_Tmp vwa_Control_Data[0] vwa_Buff_Send_Word[0] vba_Send[1]
; 正常完了かチェック
558   LD      vba_Send[1]
      MPS
      ANI     vba_Send[2]
      SET     vb_Tmp_OK
      MRD
      AND     vba_Send[2]
      MOV     K119 ERROR_ID
      SET     vb_Tmp_Error
      MOV     vwa_Control_Data[1] ow_UNIT_ERR_CODE
      SET     vb_Tmp_Unit_Error
      MPP
      RST     vb_Send_Ready
; インデックスレジスタ復帰処理
595   LD      SM400
      MOV     vw_ZTmp Z9
; FB完了処理
605   LD      vb_Program_End
      MPS
      AND     vb_Tmp_OK
      PLS     FB_OK
      MRD
      AND     vb_Tmp_Error
      PLS     FB_ERROR
      MRD
      AND     vb_Tmp_Unit_Error
      PLS     ob_UNIT_ERROR
      MPP
      RST     vb_Tmp_OK
      RST     vb_Tmp_Error
      RST     vb_Tmp_Unit_Error
      RST     FB_ENO
      RST     vb_Program_End
      RST     vba_Send[0]
      RST     vba_Send[1]
      RST     vba_Send[2]
      RST     vb_UDE
644   LD      vb_Tmp_OK
      OR      vb_Tmp_Error
      OR      vb_Tmp_Unit_Error
      SET     vb_Program_End
END_FUNCTION_BLOCK

FUNCTION_BLOCK P+TAKAYA-TR3-E_Connect  // TCP/IP接続処理(ソケットオープン)
VAR_INPUT
  FB_EN : BOOL;  (* 実行命令 *)
  iw_Start_IO_No : INT;  (* 先頭I/ONo. *)
  iw_Connection_No : INT;  (* コネクションNo. *)
END_VAR
VAR_OUTPUT
  FB_OK : BOOL;  (* 正常完了 *)
  FB_ERROR : BOOL;  (* 異常完了フラグ *)
  ERROR_ID : INT;  (* エラーコード *)
  FB_ENO : BOOL;  (* 実行状態 *)
END_VAR
VAR
  vb_Program_Init : BOOL;  (* プログラム実行前初期化 *)
  vb_Check_Input : BOOL;  (* 入力範囲判定 *)
  vb_Open_Flg : BOOL;  (* オープン完了信号監視フラグ *)
  vb_Connect_Open_Check : BOOL;  (* コネクションオープンチェック *)
  vwa_Control_Data : ARRAY [0..9] OF INT;  (* コントロールデータ *)
  vb_Connect_Set : BOOL;  (* コネクション値設定 *)
  vb_Tmp_Error : BOOL;  (* エラー内部フラグ *)
  vb_Tmp_OK : BOOL;  (* FB完了内部フラグ *)
  vw_Start_IO_No_Tmp : INT;  (* 先頭I/ONo.内部 *)
  vw_Connection_No_Tmp : INT;  (* コネクションNo.内部 *)
  vb_Tmp_Unit_Error : BOOL;  (* 機器エラー内部フラグ *)
  vb_Program_End : BOOL;  (* FB終了処理内部フラグ *)
  vw_Connection_Flg : INT;  (* コネクションフラグ *)
END_VAR
VAR_OUTPUT
  ob_UNIT_ERROR : BOOL;  (* 機器異常完了フラグ *)
  ow_UNIT_ERR_CODE : INT;  (* 機器エラーコード *)
END_VAR
VAR
  vba_Open : ARRAY [0..2] OF BOOL;  (* コネクションオープンフラグ *)
  vb_UDE : BOOL;  (* QnUDE(H)認識フラグ *)
  vw_ZTmp : INT;  (* インデックスレジスタ一時退避 *)
END_VAR
; ＊＊＊＊＊＊＊＊＊＊＊＊＊＊＊＊＊＊＊＊
; ＊FB名称:P+TAKAYA-TR3-E_Connect
; ＊機能:TCP/IP接続処理(ソケットオープン)
; ＊バージョン:Ver1.00A
; ＊＊＊＊＊＊＊＊＊＊＊＊＊＊＊＊＊＊＊＊
; FB非実行時接点OFF
108   LDI     FB_EN
      RST     vb_Program_Init
      RST     vb_Check_Input
      RST     vb_Connect_Set
      RST     vb_Connect_Open_Check
; FB実行開始時
126   LDP     FB_EN
      SET     FB_ENO
      SET     vb_Program_Init
; プログラム実行前初期化
146   LD      vb_Program_Init
      MOV     K0 ERROR_ID
      MOV     K0 ow_UNIT_ERR_CODE
      MOV     K0 vw_Connection_Flg
      FMOV    K0 vwa_Control_Data[0] K2
      SET     vb_Check_Input
      RST     vb_Program_Init
; 入力範囲判定
170   LD      vb_Check_Input
      MPS
      AND=    H0FFFF iw_Start_IO_No
      SET     vb_UDE
      MRD
      ANI     vb_UDE
      LD<     iw_Connection_No K1
      OR=     iw_Connection_No K8
      OR>     iw_Connection_No K15
      ANB
      SET     vb_Tmp_Error
      MOV     K100 ERROR_ID
      MRD
      AND     vb_UDE
      LD<     iw_Connection_No K1
      OR>     iw_Connection_No K16
      ANB
      SET     vb_Tmp_Error
      MOV     K100 ERROR_ID
      MRD
      ANI     vb_Tmp_Error
      MOV     iw_Connection_No vw_Connection_No_Tmp
      MOV     iw_Start_IO_No vw_Start_IO_No_Tmp
      SET     vb_Connect_Set
      MPP
      RST     vb_Check_Input
; インデックスレジスタ一時退避
237   LD      SM400
      MOV     Z9 vw_ZTmp
      MOV     K0 Z9
; インデックスレジスタ値格納
257   LD      FB_ENO
      MPS
      ANI     vb_UDE
      MOV     vw_Start_IO_No_Tmp Z9
      SFR     Z9 K4
      MPP
      AND     vb_UDE
      MOV     K0 Z9
; コネクション値設定
284   LD      vb_Connect_Set
      -       vw_Connection_No_Tmp K1 vw_Connection_Flg
      SET     vb_Connect_Open_Check
      RST     vb_Connect_Set
; コネクションオープンチェック
310   LD      vb_Connect_Open_Check
      MPS
      ANI     vb_UDE
      TEST    U0\G20480Z9 vw_Connection_Flg vb_Open_Flg
      MRD
      AND     vb_UDE
      TEST    SD1282 vw_Connection_Flg vb_Open_Flg
      MRD
      ANI     vb_Open_Flg
      SET     vba_Open[0]
      MRD
      AND     vb_Open_Flg
      SET     vb_Tmp_OK
      MPP
      RST     vb_Connect_Open_Check
; コネクションオープン処理
355   LD      vba_Open[0]
      MPS
      ANI     vb_UDE
      ZP.OPEN "U0Z9" vw_Connection_No_Tmp vwa_Control_Data[0] vba_Open[1]
      MPP
      AND     vb_UDE
      SP.SOCOPEN "U0" vw_Connection_No_Tmp vwa_Control_Data[0] vba_Open[1]
; 正常終了かチェック
397   LD      vba_Open[1]
      MPS
      ANI     vba_Open[2]
      SET     vb_Tmp_OK
      MRD
      AND     vba_Open[2]
      MOV     K201 ERROR_ID
      SET     vb_Tmp_Error
      MOV     vwa_Control_Data[1] ow_UNIT_ERR_CODE
      SET     vb_Tmp_Unit_Error
      MPP
      RST     vb_Open_Flg
      RST     vba_Open[0]
; インデックスレジスタ復帰処理
436   LD      SM400
      MOV     vw_ZTmp Z9
; FB完了処理
446   LD      vb_Program_End
      MPS
      AND     vb_Tmp_OK
      PLS     FB_OK
      MRD
      AND     vb_Tmp_Error
      PLS     FB_ERROR
      MRD
      AND     vb_Tmp_Unit_Error
      PLS     ob_UNIT_ERROR
      MPP
      RST     vb_Tmp_OK
      RST     vb_Tmp_Error
      RST     vb_Tmp_Unit_Error
      RST     FB_ENO
      RST     vb_Program_End
      RST     vba_Open[0]
      RST     vba_Open[1]
      RST     vba_Open[2]
      RST     vb_UDE
485   LD      vb_Tmp_OK
      OR      vb_Tmp_Error
      OR      vb_Tmp_Unit_Error
      SET     vb_Program_End
END_FUNCTION_BLOCK

FUNCTION_BLOCK P+TAKAYA-TR3-E_Disconnect  // TCP/IP切断処理(ソケットクローズ)
VAR_INPUT
  FB_EN : BOOL;  (* 実行命令 *)
  iw_Start_IO_No : INT;  (* 先頭I/ONo. *)
  iw_Connection_No : INT;  (* コネクションNo. *)
END_VAR
VAR_OUTPUT
  FB_OK : BOOL;  (* 正常完了 *)
  FB_ERROR : BOOL;  (* 異常完了フラグ *)
  ERROR_ID : INT;  (* エラーコード *)
  FB_ENO : BOOL;  (* 実行状態 *)
END_VAR
VAR
  vb_Program_Init : BOOL;  (* プログラム実行前初期化 *)
  vb_Check_Input : BOOL;  (* 入力範囲判定 *)
  vb_Open_Flg : BOOL;  (* オープン完了信号監視フラグ *)
  vb_Connect_Open_Check : BOOL;  (* コネクションオープンチェック *)
  vwa_Control_Data : ARRAY [0..1] OF INT;  (* コントロールデータ *)
  vb_Connect_Set : BOOL;  (* コネクション値設定 *)
  vb_Tmp_Error : BOOL;  (* エラー内部フラグ *)
  vb_Tmp_OK : BOOL;  (* FB完了内部フラグ *)
  vw_Start_IO_No_Tmp : INT;  (* 先頭I/ONo.内部 *)
  vw_Connection_No_Tmp : INT;  (* コネクションNo.内部 *)
  vb_Tmp_Unit_Error : BOOL;  (* 機器エラー内部フラグ *)
  vb_Program_End : BOOL;  (* FB終了処理内部フラグ *)
  vw_Connection_Flg : INT;  (* コネクションフラグ *)
END_VAR
VAR_OUTPUT
  ob_UNIT_ERROR : BOOL;  (* 機器異常完了フラグ *)
  ow_UNIT_ERR_CODE : INT;  (* 機器エラーコード *)
END_VAR
VAR
  vba_Close : ARRAY [0..2] OF BOOL;  (* コネクションクローズフラグ *)
  vb_UDE : BOOL;  (* QnUDE(H)認識フラグ *)
  vw_ZTmp : INT;  (* インデックスレジスタ一時退避 *)
  vb_Rcv_Flg : BOOL;  (* オープン要求信号監視フラグ *)
END_VAR
; ＊＊＊＊＊＊＊＊＊＊＊＊＊＊＊＊＊＊＊＊
; ＊FB名称:P+TAKAYA-TR3-E_Disconnect
; ＊機能:TCP/IP切断処理(ソケットクローズ)
; ＊バージョン:Ver1.00A
; ＊＊＊＊＊＊＊＊＊＊＊＊＊＊＊＊＊＊＊＊
; FB非実行時接点OFF
109   LDI     FB_EN
      RST     vb_Program_Init
      RST     vb_Check_Input
      RST     vb_Connect_Set
      RST     vb_Connect_Open_Check
; FB実行開始時
127   LDP     FB_EN
      SET     FB_ENO
      SET     vb_Program_Init
; プログラム実行前初期化
147   LD      vb_Program_Init
      MOV     K0 ERROR_ID
      MOV     K0 ow_UNIT_ERR_CODE
      MOV     K0 vw_Connection_Flg
      FMOV    K0 vwa_Control_Data[0] K2
      SET     vb_Check_Input
      RST     vb_Program_Init
; 入力範囲判定
171   LD      vb_Check_Input
      MPS
      AND=    H0FFFF iw_Start_IO_No
      SET     vb_UDE
      MRD
      ANI     vb_UDE
      LD<     iw_Connection_No K1
      OR=     iw_Connection_No K8
      OR>     iw_Connection_No K15
      ANB
      SET     vb_Tmp_Error
      MOV     K100 ERROR_ID
      MRD
      AND     vb_UDE
      LD<     iw_Connection_No K1
      OR>     iw_Connection_No K16
      ANB
      SET     vb_Tmp_Error
      MOV     K100 ERROR_ID
      MRD
      ANI     vb_Tmp_Error
      MOV     iw_Connection_No vw_Connection_No_Tmp
      MOV     iw_Start_IO_No vw_Start_IO_No_Tmp
      SET     vb_Connect_Set
      MPP
      RST     vb_Check_Input
; インデックスレジスタ一時退避
238   LD      SM400
      MOV     Z9 vw_ZTmp
      MOV     K0 Z9
; インデックスレジスタ値格納
258   LD      FB_ENO
      MPS
      ANI     vb_UDE
      MOV     vw_Start_IO_No_Tmp Z9
      SFR     Z9 K4
      MPP
      AND     vb_UDE
      MOV     K0 Z9
; コネクション値設定
285   LD      vb_Connect_Set
      -       vw_Connection_No_Tmp K1 vw_Connection_Flg
      SET     vb_Connect_Open_Check
      RST     vb_Connect_Set
; コネクションオープンチェック
311   LD      vb_Connect_Open_Check
      MPS
      ANI     vb_UDE
      TEST    U0\G20480Z9 vw_Connection_Flg vb_Open_Flg
      TEST    U0\G20482Z9 vw_Connection_Flg vb_Rcv_Flg
      MRD
      AND     vb_UDE
      TEST    SD1282 vw_Connection_Flg vb_Open_Flg
      TEST    SD1284 vw_Connection_Flg vb_Rcv_Flg
      MRD
      ANI     vb_Open_Flg
      ANI     vb_Rcv_Flg
      SET     vb_Tmp_OK
      MRD
      LD      vb_Open_Flg
      OR      vb_Rcv_Flg
      ANB
      SET     vba_Close[0]
      MPP
      RST     vb_Connect_Open_Check
; コネクションクローズ処理
371   LD      vba_Close[0]
      MPS
      ANI     vb_UDE
      ZP.CLOSE "U0Z9" vw_Connection_No_Tmp vwa_Control_Data[0] vba_Close[1]
      MPP
      AND     vb_UDE
      SP.SOCCLOSE "U0" vw_Connection_No_Tmp vwa_Control_Data[0] vba_Close[1]
; 正常終了かチェック
414   LD      vba_Close[1]
      MPS
      ANI     vba_Close[2]
      SET     vb_Tmp_OK
      MRD
      AND     vba_Close[2]
      MOV     K202 ERROR_ID
      SET     vb_Tmp_Error
      MOV     vwa_Control_Data[1] ow_UNIT_ERR_CODE
      SET     vb_Tmp_Unit_Error
      MPP
      RST     vb_Open_Flg
      RST     vba_Close[0]
; インデックスレジスタ復帰処理
453   LD      SM400
      MOV     vw_ZTmp Z9
; FB完了処理
463   LD      vb_Program_End
      MPS
      AND     vb_Tmp_OK
      PLS     FB_OK
      MRD
      AND     vb_Tmp_Error
      PLS     FB_ERROR
      MRD
      AND     vb_Tmp_Unit_Error
      PLS     ob_UNIT_ERROR
      MPP
      RST     vb_Tmp_OK
      RST     vb_Tmp_Error
      RST     vb_Tmp_Unit_Error
      RST     FB_ENO
      RST     vb_Program_End
      RST     vba_Close[0]
      RST     vba_Close[1]
      RST     vba_Close[2]
      RST     vb_UDE
502   LD      vb_Tmp_OK
      OR      vb_Tmp_Error
      OR      vb_Tmp_Unit_Error
      SET     vb_Program_End
END_FUNCTION_BLOCK

FUNCTION_BLOCK P+TAKAYA-TR3-E_Inventory  // Inventory
VAR_INPUT
  FB_EN : BOOL;  (* 実行命令 *)
  iw_Start_IO_No : INT;  (* 先頭I/ONo. *)
  iw_Connection_No : INT;  (* コネクションNo. *)
END_VAR
VAR_OUTPUT
  FB_OK : BOOL;  (* 正常完了 *)
  FB_ERROR : BOOL;  (* 異常完了フラグ *)
  ERROR_ID : INT;  (* エラーコード *)
  FB_ENO : BOOL;  (* 実行状態 *)
END_VAR
VAR
  vb_Program_Init : BOOL;  (* プログラム実行前初期化 *)
  vb_Check_Input : BOOL;  (* 入力範囲判定 *)
  vb_Tmp_Error : BOOL;  (* エラー内部フラグ *)
  vb_Tmp_OK : BOOL;  (* FB完了内部フラグ *)
  vw_Start_IO_No_Tmp : INT;  (* 先頭I/ONo.内部 *)
  vw_Connection_No_Tmp : INT;  (* コネクションNo.内部 *)
  vb_Tmp_Unit_Error : BOOL;  (* 機器エラー内部フラグ *)
  vb_Program_End : BOOL;  (* FB終了処理内部フラグ *)
END_VAR
VAR_OUTPUT
  ob_UNIT_ERROR : BOOL;  (* 機器異常完了フラグ *)
  ow_UNIT_ERR_CODE : INT;  (* 機器エラーコード *)
END_VAR
VAR
  vwa_Control_Data : ARRAY [0..1] OF INT;  (* コントロールデータ *)
  vb_Sum_Calc : BOOL;  (* SUM計算開始フラグ *)
  vb_Send_Ready : BOOL;  (* 送信準備完了フラグ *)
  vwa_Send_Sum : ARRAY [0..1] OF INT;  (* 送信SUM合計値 *)
  vwa_Buff_Send_Byte : ARRAY [0..9] OF INT;  (* 送信バッファバイト *)
  vba_Send : ARRAY [0..2] OF BOOL;  (* 送信処理フラグ *)
  vb_UDE : BOOL;  (* QnUDE(H)認識フラグ *)
END_VAR
VAR_INPUT
  ib_AFI_Flag : BOOL;  (* AFI指定 *)
END_VAR
VAR
  vb_RFID_Option : BOOL;  (* RFタグオプションフラグ *)
  vw_RFID_Option_Tmp : INT;  (* RFタグオプション *)
  vwa_Buff_Send_Word : ARRAY [0..5] OF INT;  (* 送信バッファワード *)
  vb_Join_Byte : BOOL;  (* バイト単位結合 *)
  vw_ZTmp : INT;  (* インデックスレジスタ一時退避 *)
END_VAR
; ＊＊＊＊＊＊＊＊＊＊＊＊＊＊＊＊＊＊＊＊
; ＊FB名称:P+TAKAYA-TR3-E_Inventory
; ＊機能:Inventory
; ＊バージョン:Ver1.00A
; ＊＊＊＊＊＊＊＊＊＊＊＊＊＊＊＊＊＊＊＊
; FB非実行時接点OFF
97    LDI     FB_EN
      RST     vb_Program_Init
      RST     vb_Check_Input
      RST     vb_Join_Byte
      RST     vb_RFID_Option
      RST     vb_Sum_Calc
      RST     vb_Send_Ready
; FB実行開始時
119   LDP     FB_EN
      SET     FB_ENO
      SET     vb_Program_Init
; プログラム実行前初期化
139   LD      vb_Program_Init
      MOV     K0 ERROR_ID
      MOV     K0 ow_UNIT_ERR_CODE
      MOV     K0 vw_RFID_Option_Tmp
      FMOV    K0 vwa_Buff_Send_Byte[0] K10
      FMOV    K0 vwa_Buff_Send_Word[0] K6
      FMOV    K0 vwa_Control_Data[0] K2
      FMOV    K0 vwa_Send_Sum[0] K2
      SET     vb_Check_Input
      RST     vb_Program_Init
; 入力範囲判定
175   LD      vb_Check_Input
      MPS
      AND=    H0FFFF iw_Start_IO_No
      SET     vb_UDE
      MRD
      ANI     vb_UDE
      LD<     iw_Connection_No K2
      OR=     iw_Connection_No K9
      OR>     iw_Connection_No K16
      ANB
      SET     vb_Tmp_Error
      MOV     K100 ERROR_ID
      MRD
      AND     vb_UDE
      LD<     iw_Connection_No K1
      OR>     iw_Connection_No K16
      ANB
      SET     vb_Tmp_Error
      MOV     K100 ERROR_ID
      MRD
      ANI     vb_Tmp_Error
      MOV     iw_Connection_No vw_Connection_No_Tmp
      MOV     iw_Start_IO_No vw_Start_IO_No_Tmp
      SET     vba_Send[0]
      MPP
      RST     vb_Check_Input
; インデックスレジスタ一時退避
242   LD      SM400
      MOV     Z9 vw_ZTmp
      MOV     K0 Z9
; インデックスレジスタ値格納
262   LD      FB_ENO
      MPS
      ANI     vb_UDE
      MOV     vw_Start_IO_No_Tmp Z9
      SFR     Z9 K4
      MPP
      AND     vb_UDE
      MOV     K0 Z9
; 送信フォーマット作成
290   LD      vba_Send[0]
      MOV     H2 vwa_Buff_Send_Byte[1]
      MOV     H0 vwa_Buff_Send_Byte[2]
      MOV     H78 vwa_Buff_Send_Byte[3]
      MOV     H2 vwa_Buff_Send_Byte[4]
      MOV     H1 vwa_Buff_Send_Byte[5]
      MOV     H3 vwa_Buff_Send_Byte[7]
      MOV     H0D vwa_Buff_Send_Byte[9]
      SET     vb_RFID_Option
      RST     vba_Send[0]
; RFタグのオプション設定
323   LD      vb_RFID_Option
      MPS
      AND     ib_AFI_Flag
      BSET    vw_RFID_Option_Tmp K5
      MPP
      BSET    vw_RFID_Option_Tmp K6
      MOV     vw_RFID_Option_Tmp vwa_Buff_Send_Byte[6]
      SET     vb_Sum_Calc
      RST     vb_RFID_Option
; SUMの計算
348   LD      vb_Sum_Calc
      WSUM    vwa_Buff_Send_Byte[1] vwa_Send_Sum[0] K7
      DAND    H0FF vwa_Send_Sum[0]
      MOV     vwa_Send_Sum[0] vwa_Buff_Send_Byte[8]
      SET     vb_Join_Byte
      RST     vb_Sum_Calc
; バイト単位データ結合
376   LD      vb_Join_Byte
      BTOW    vwa_Buff_Send_Byte[1] vwa_Buff_Send_Word[1] K9
      MOV     K9 vwa_Buff_Send_Word[0]
      SET     vb_Send_Ready
      RST     vb_Join_Byte
; 送信処理
394   LD      vb_Send_Ready
      MPS
      ANI     vb_UDE
      ZP.BUFSND "U0Z9" vw_Connection_No_Tmp vwa_Control_Data[0] vwa_Buff_Send_Word[0] vba_Send[1]
      MPP
      AND     vb_UDE
      SP.SOCSND "U0" vw_Connection_No_Tmp vwa_Control_Data[0] vwa_Buff_Send_Word[0] vba_Send[1]
; 正常完了かチェック
438   LD      vba_Send[1]
      MPS
      ANI     vba_Send[2]
      SET     vb_Tmp_OK
      MRD
      AND     vba_Send[2]
      MOV     K119 ERROR_ID
      SET     vb_Tmp_Error
      MOV     vwa_Control_Data[1] ow_UNIT_ERR_CODE
      SET     vb_Tmp_Unit_Error
      MPP
      RST     vb_Send_Ready
; インデックスレジスタ復帰処理
475   LD      SM400
      MOV     vw_ZTmp Z9
; FB完了処理
485   LD      vb_Program_End
      MPS
      AND     vb_Tmp_OK
      PLS     FB_OK
      MRD
      AND     vb_Tmp_Error
      PLS     FB_ERROR
      MRD
      AND     vb_Tmp_Unit_Error
      PLS     ob_UNIT_ERROR
      MPP
      RST     vb_Tmp_OK
      RST     vb_Tmp_Error
      RST     vb_Tmp_Unit_Error
      RST     FB_ENO
      RST     vb_Program_End
      RST     vba_Send[0]
      RST     vba_Send[1]
      RST     vba_Send[2]
      RST     vb_UDE
524   LD      vb_Tmp_OK
      OR      vb_Tmp_Error
      OR      vb_Tmp_Unit_Error
      SET     vb_Program_End
END_FUNCTION_BLOCK

FUNCTION_BLOCK P+TAKAYA-TR3-E_ReadBytes  // ReadBytes
VAR_INPUT
  FB_EN : BOOL;  (* 実行命令 *)
  iw_Start_IO_No : INT;  (* 先頭I/ONo. *)
  iw_Connection_No : INT;  (* コネクションNo. *)
END_VAR
VAR_OUTPUT
  FB_OK : BOOL;  (* 正常完了 *)
  FB_ERROR : BOOL;  (* 異常完了フラグ *)
  ERROR_ID : INT;  (* エラーコード *)
  FB_ENO : BOOL;  (* 実行状態 *)
END_VAR
VAR
  vb_Program_Init : BOOL;  (* プログラム実行前初期化 *)
  vb_Check_Input : BOOL;  (* 入力範囲判定 *)
  vb_Tmp_Error : BOOL;  (* エラー内部フラグ *)
  vb_Tmp_OK : BOOL;  (* FB完了内部フラグ *)
  vw_Start_IO_No_Tmp : INT;  (* 先頭I/ONo.内部 *)
  vw_Connection_No_Tmp : INT;  (* コネクションNo.内部 *)
  vb_Tmp_Unit_Error : BOOL;  (* 機器エラー内部フラグ *)
  vb_Program_End : BOOL;  (* FB終了処理内部フラグ *)
END_VAR
VAR_OUTPUT
  ob_UNIT_ERROR : BOOL;  (* 機器異常完了フラグ *)
  ow_UNIT_ERR_CODE : INT;  (* 機器エラーコード *)
END_VAR
VAR
  vwa_Control_Data : ARRAY [0..1] OF INT;  (* コントロールデータ *)
  vb_Sum_Calc : BOOL;  (* SUM計算開始フラグ *)
  vb_Send_Ready : BOOL;  (* 送信準備完了フラグ *)
  vwa_Send_Sum : ARRAY [0..1] OF INT;  (* 送信SUM合計値 *)
  vba_Send : ARRAY [0..2] OF BOOL;  (* 送信処理フラグ *)
  vb_UDE : BOOL;  (* QnUDE(H)認識フラグ *)
  vb_RFID_Option : BOOL;  (* RFタグオプションフラグ *)
  vw_RFID_Option_Tmp : INT;  (* RFタグオプション *)
  vb_Join_Byte : BOOL;  (* バイト単位結合 *)
  vwa_Buff_Send_Byte : ARRAY [0..19] OF INT;  (* 送信バッファバイト *)
  vwa_Buff_Send_Word : ARRAY [0..10] OF INT;  (* 送信バッファワード *)
END_VAR
VAR_INPUT
  iwa_UID : INT;  (* UID *)
  ib_UID_Flag : BOOL;  (* UID指定 *)
END_VAR
VAR
  vw_Byte_Size_Tmp : INT;  (* 読み取りバイト数内部 *)
  vwa_UID_Tmp : ARRAY [0..7] OF INT;  (* UID内部 *)
END_VAR
VAR_INPUT
  iw_Byte_Size : INT;  (* 読み取りバイト数 *)
  iw_Start_Blk_No : INT;  (* 読み取り開始ブロック番号 *)
END_VAR
VAR
  vw_Start_Blk_No_Tmp : INT;  (* 読み取り開始ブロック番号内部 *)
  vw_ZTmp : INT;  (* インデックスレジスタ一時退避 *)
END_VAR
; ＊＊＊＊＊＊＊＊＊＊＊＊＊＊＊＊＊＊＊＊
; ＊FB名称:P+TAKAYA-TR3-E_ReadBytes
; ＊機能:ReadBytes
; ＊バージョン:Ver1.00A
; ＊＊＊＊＊＊＊＊＊＊＊＊＊＊＊＊＊＊＊＊
; FB非実行時接点OFF
97    LDI     FB_EN
      RST     vb_Program_Init
      RST     vb_Check_Input
      RST     vb_Join_Byte
      RST     vb_RFID_Option
      RST     vb_Sum_Calc
      RST     vb_Send_Ready
; FB実行開始時
119   LDP     FB_EN
      SET     FB_ENO
      SET     vb_Program_Init
; プログラム実行前初期化
139   LD      vb_Program_Init
      MOV     K0 ERROR_ID
      MOV     K0 ow_UNIT_ERR_CODE
      MOV     K0 vw_RFID_Option_Tmp
      MOV     K0 vw_Start_Blk_No_Tmp
      MOV     K0 vw_Byte_Size_Tmp
      FMOV    K0 vwa_UID_Tmp[0] K8
      FMOV    K0 vwa_Buff_Send_Byte[0] K20
      FMOV    K0 vwa_Buff_Send_Word[0] K11
      FMOV    K0 vwa_Control_Data[0] K2
      FMOV    K0 vwa_Send_Sum[0] K2
      SET     vb_Check_Input
      RST     vb_Program_Init
; 入力範囲判定
183   LD      vb_Check_Input
      MPS
      AND=    H0FFFF iw_Start_IO_No
      SET     vb_UDE
      MRD
      ANI     vb_UDE
      LD<     iw_Connection_No K2
      OR=     iw_Connection_No K9
      OR>     iw_Connection_No K16
      ANB
      SET     vb_Tmp_Error
      MOV     K100 ERROR_ID
      MRD
      AND     vb_UDE
      LD<     iw_Connection_No K1
      OR>     iw_Connection_No K16
      ANB
      SET     vb_Tmp_Error
      MOV     K100 ERROR_ID
      MRD
      LD<     iw_Start_Blk_No K0
      OR>     iw_Start_Blk_No K255
      ANB
      SET     vb_Tmp_Error
      MOV     K111 ERROR_ID
      MRD
      LD<     iw_Byte_Size K1
      OR>     iw_Byte_Size K254
      ANB
      SET     vb_Tmp_Error
      MOV     K113 ERROR_ID
      MRD
      AND     ib_UID_Flag
      WTOB    iwa_UID vwa_UID_Tmp[0] K8
      MRD
      ANI     vb_Tmp_Error
      MOV     iw_Connection_No vw_Connection_No_Tmp
      MOV     iw_Start_IO_No vw_Start_IO_No_Tmp
      MOV     iw_Start_Blk_No vw_Start_Blk_No_Tmp
      MOV     iw_Byte_Size vw_Byte_Size_Tmp
      SET     vba_Send[0]
      MPP
      RST     vb_Check_Input
; インデックスレジスタ一時退避
285   LD      SM400
      MOV     Z9 vw_ZTmp
      MOV     K0 Z9
; インデックスレジスタ値格納
305   LD      FB_ENO
      MPS
      ANI     vb_UDE
      MOV     vw_Start_IO_No_Tmp Z9
      SFR     Z9 K4
      MPP
      AND     vb_UDE
      MOV     K0 Z9
; 送信フォーマット作成
333   LD      vba_Send[0]
      MOV     H2 vwa_Buff_Send_Byte[1]
      MOV     H0 vwa_Buff_Send_Byte[2]
      MOV     H78 vwa_Buff_Send_Byte[3]
      MPS
      AND     ib_UID_Flag
      MOV     H0C vwa_Buff_Send_Byte[4]
      MRD
      ANI     ib_UID_Flag
      MOV     H4 vwa_Buff_Send_Byte[4]
      MPP
      MOV     H0A0 vwa_Buff_Send_Byte[5]
      MOV     vw_Start_Blk_No_Tmp vwa_Buff_Send_Byte[6]
      MOV     vw_Byte_Size_Tmp vwa_Buff_Send_Byte[7]
      MPS
      AND     ib_UID_Flag
      BMOV    vwa_UID_Tmp[0] vwa_Buff_Send_Byte[9] K8
      MOV     H3 vwa_Buff_Send_Byte[17]
      MOV     H0D vwa_Buff_Send_Byte[19]
      MRD
      ANI     ib_UID_Flag
      MOV     H3 vwa_Buff_Send_Byte[9]
      MOV     H0D vwa_Buff_Send_Byte[11]
      MPP
      SET     vb_RFID_Option
      RST     vba_Send[0]
; RFタグのオプション設定
394   LD      vb_RFID_Option
      MPS
      AND     ib_UID_Flag
      BSET    vw_RFID_Option_Tmp K0
      MPP
      MOV     vw_RFID_Option_Tmp vwa_Buff_Send_Byte[8]
      SET     vb_Sum_Calc
      RST     vb_RFID_Option
; SUMの計算
416   LD      vb_Sum_Calc
      MPS
      AND     ib_UID_Flag
      WSUM    vwa_Buff_Send_Byte[1] vwa_Send_Sum[0] K17
      MRD
      ANI     ib_UID_Flag
      WSUM    vwa_Buff_Send_Byte[1] vwa_Send_Sum[0] K9
      MPP
      DAND    H0FF vwa_Send_Sum[0]
      MPS
      AND     ib_UID_Flag
      MOV     vwa_Send_Sum[0] vwa_Buff_Send_Byte[18]
      MRD
      ANI     ib_UID_Flag
      MOV     vwa_Send_Sum[0] vwa_Buff_Send_Byte[10]
      MPP
      SET     vb_Join_Byte
      RST     vb_Sum_Calc
; バイト単位データ結合
464   LD      vb_Join_Byte
      MPS
      AND     ib_UID_Flag
      BTOW    vwa_Buff_Send_Byte[1] vwa_Buff_Send_Word[1] K19
      MOV     K19 vwa_Buff_Send_Word[0]
      MRD
      ANI     ib_UID_Flag
      BTOW    vwa_Buff_Send_Byte[1] vwa_Buff_Send_Word[1] K11
      MOV     K11 vwa_Buff_Send_Word[0]
      MPP
      SET     vb_Send_Ready
      RST     vb_Join_Byte
; 送信処理
495   LD      vb_Send_Ready
      MPS
      ANI     vb_UDE
      ZP.BUFSND "U0Z9" vw_Connection_No_Tmp vwa_Control_Data[0] vwa_Buff_Send_Word[0] vba_Send[1]
      MPP
      AND     vb_UDE
      SP.SOCSND "U0" vw_Connection_No_Tmp vwa_Control_Data[0] vwa_Buff_Send_Word[0] vba_Send[1]
; 正常完了かチェック
539   LD      vba_Send[1]
      MPS
      ANI     vba_Send[2]
      SET     vb_Tmp_OK
      MRD
      AND     vba_Send[2]
      MOV     K119 ERROR_ID
      SET     vb_Tmp_Error
      MOV     vwa_Control_Data[1] ow_UNIT_ERR_CODE
      SET     vb_Tmp_Unit_Error
      MPP
      RST     vb_Send_Ready
; インデックスレジスタ復帰処理
576   LD      SM400
      MOV     vw_ZTmp Z9
; FB完了処理
586   LD      vb_Program_End
      MPS
      AND     vb_Tmp_OK
      PLS     FB_OK
      MRD
      AND     vb_Tmp_Error
      PLS     FB_ERROR
      MRD
      AND     vb_Tmp_Unit_Error
      PLS     ob_UNIT_ERROR
      MPP
      RST     vb_Tmp_OK
      RST     vb_Tmp_Error
      RST     vb_Tmp_Unit_Error
      RST     FB_ENO
      RST     vb_Program_End
      RST     vba_Send[0]
      RST     vba_Send[1]
      RST     vba_Send[2]
      RST     vb_UDE
625   LD      vb_Tmp_OK
      OR      vb_Tmp_Error
      OR      vb_Tmp_Unit_Error
      SET     vb_Program_End
END_FUNCTION_BLOCK

FUNCTION_BLOCK P+TAKAYA-TR3-E_Response  // 受信設定
VAR_INPUT
  FB_EN : BOOL;  (* 実行命令 *)
  iw_Start_IO_No : INT;  (* 先頭I/ONo. *)
  iw_Connection_No : INT;  (* コネクションNo. *)
END_VAR
VAR_OUTPUT
  FB_ENO : BOOL;  (* 実行状態 *)
  FB_OK : BOOL;  (* 正常完了 *)
  FB_ERROR : BOOL;  (* 異常完了フラグ *)
  ERROR_ID : INT;  (* エラーコード *)
  ob_UNIT_ERROR : BOOL;  (* 機器異常完了フラグ *)
  ow_UNT_ERR_CODE1 : INT;  (* 機器エラーコード1 *)
  ow_UNT_ERR_CODE2 : INT;  (* 機器エラーコード2 *)
  ow_RFID_Res_Type : INT;  (* 受信動作タイプ *)
  ow_RFID_ID : INT;  (* 受信ID *)
  ow_RFID_UID_Len : INT;  (* 受信UIDバイト数 *)
  ow_RFID_Data_Len : INT;  (* 受信バイト数 *)
  ow_RFID_UII_Len : INT;  (* 受信UIIバイト数 *)
  owa_RFID_UID : INT;  (* 受信UID *)
  owa_RFID_Data : INT;  (* 受信データ *)
  owa_RFID_UII : INT;  (* 受信UII *)
END_VAR
VAR
  vb_UDE : BOOL;  (* 内蔵Ethernet *)
  vb_Tmp_OK : BOOL;  (* 正常完了内部フラグ *)
  vb_Tmp_Error : BOOL;  (* 異常完了内部フラグ *)
  vb_Tmp_Unit_Error : BOOL;  (* 機器異常完了内部フラグ *)
  vb_Program_Init : BOOL;  (* プログラム実行前初期化 *)
  vb_Check_Input : BOOL;  (* 入力範囲判定 *)
  vb_Check_Cmd : BOOL;  (* 受信コマンドチェック *)
  vb_UID_Cmd : BOOL;  (* UIDコマンド受信 *)
  vb_EPC_Cmd : BOOL;  (* EPCコマンド受信 *)
  vb_Other_Cmd : BOOL;  (* Otherコマンド受信 *)
  vb_Program_End : BOOL;  (* FB終了処理 *)
  vb_Receiving : BOOL;  (* 受信中フラグ *)
  vw_ZTmp : INT;  (* 内部Zデバイス *)
  vd_DTmp1 : DINT;  (* 内部Dデバイス1 *)
  vd_DTmp2 : DINT;  (* 内部Dデバイス2 *)
  vd_DTmp5 : DINT;  (* 内部Dデバイス5 *)
  vd_DTmp3 : DINT;  (* 内部Dデバイス3 *)
  vd_DTmp4 : DINT;  (* 内部Dデバイス4 *)
  vba_Rcv : ARRAY [0..2] OF BOOL;  (* 受信処理 *)
  vb_Rcv_End : BOOL;  (* 受信処理終了 *)
  vb_Fin_Rcv : BOOL;  (* コマンド全データ受信終了 *)
  vb_Rcv_Flg : BOOL;  (* 受信データ有無 *)
  vd_Rcv_Pos : DINT;  (* 受信バッファ読出し位置 *)
  vwa_Rcv_Buf : ARRAY [0..1023] OF INT;  (* 受信バッファ(ワード単位) *)
  vwa_Rcv_Data_Byte : ARRAY [0..2047] OF INT;  (* 受信バッファ(バイト単位) *)
  vw_Received_Len : INT;  (* 受信済みデータ長 *)
  vw_Trans_Len : INT;  (* 受信データ長 *)
  vb_Over_Rcv : BOOL;  (* 超過データ有無 *)
  vw_Over_Rcv_Len : INT;  (* 超過データ長 *)
  vwa_Next_Rcv_Data : ARRAY [0..1023] OF INT;  (* 超過データ *)
  vwa_Chk_Sum : ARRAY [0..1] OF INT;  (* サム計算値 *)
  vw_Sum_Len : INT;  (* サム値計算用データ長 *)
  vw_Rcv_Sum : INT;  (* 受信サム値 *)
  vw_Conn_Bit_Pos : INT;  (* コネクションNo.ビット位置 *)
  vw_Conn_No_Tmp : INT;  (* 内部コネクションNo. *)
  vw_Start_IO_No_Tmp : INT;  (* 内部先頭I/ONo. *)
  vwa_Ctrl_Data : ARRAY [0..1] OF INT;  (* ダミーコントロールデータ *)
  vb_Over_Recovery : BOOL;  (* 超過データ復旧 *)
  vd_Calc_Dword : DINT;  (* ダブルワード計算用 *)
  vw_Etx_Ofs : INT;  (* ETXオフセット *)
  vw_Chk_TID_Len : INT;  (* TIDデータ長計算用 *)
END_VAR
; ＊＊＊＊＊＊＊＊＊＊＊＊＊＊＊＊＊＊＊＊
; ＊FB名称:P+TAKAYA-TR3-E_Response
; ＊機能:受信設定
; ＊バージョン:Ver1.00A
; ＊＊＊＊＊＊＊＊＊＊＊＊＊＊＊＊＊＊＊＊
; 実行命令接点OFF
95    LDI     FB_EN
      ANI     vb_Receiving
      RST     vb_Program_Init
      RST     vb_Check_Cmd
      RST     vb_UID_Cmd
      RST     vb_EPC_Cmd
      RST     vb_Other_Cmd
      RST     vb_Over_Rcv
      RST     vb_Check_Input
      AND     FB_ENO
      RST     vba_Rcv[0]
        [note] FB実行中強制終了
      RST     vb_Rcv_End
      SET     vb_Tmp_Error
      MOV     K200 ERROR_ID
; FB実行開始時
141   LDP     FB_EN
      SET     FB_ENO
      SET     vb_Program_Init
; プログラム実行前初期化
161   LD      vb_Program_Init
      MOV     K0 ERROR_ID
      MOV     K0 ow_UNT_ERR_CODE1
      MOV     K0 ow_UNT_ERR_CODE2
      MOV     K0 ow_RFID_Res_Type
      MOV     K0 ow_RFID_ID
      MOV     K0 ow_RFID_Data_Len
      MOV     K0 ow_RFID_UID_Len
      MOV     K0 ow_RFID_UII_Len
      MOV     K0 vw_Trans_Len
      MPS
      ANI     vb_Over_Recovery
      MOV     K0 vw_Received_Len
      MPP
      MOV     K0 vw_Sum_Len
      MOV     K0 vw_Rcv_Sum
      MOV     K0 vw_Etx_Ofs
      MOV     K0 vw_Chk_TID_Len
      DMOV    K0 vd_Calc_Dword
      FMOV    K0 vwa_Ctrl_Data[0] K2
      FMOV    K0 vwa_Chk_Sum[0] K2
      SET     vb_Check_Input
      RST     vb_Program_Init
; 入力範囲判定
218   LD      vb_Check_Input
      RST     vb_UDE
      MPS
      AND=    H0FFFF iw_Start_IO_No
      SET     vb_UDE
      MRD
      ANI     vb_UDE
      LD<     iw_Connection_No K1
      OR=     iw_Connection_No K8
      OR>     iw_Connection_No K15
      ANB
      SET     vb_Tmp_Error
      MOV     K100 ERROR_ID
      MRD
      AND     vb_UDE
      LD<     iw_Connection_No K1
      OR>     iw_Connection_No K16
      ANB
      SET     vb_Tmp_Error
      MOV     K100 ERROR_ID
      MRD
      ANI     vb_Tmp_Error
      MOV     iw_Start_IO_No vw_Start_IO_No_Tmp
      MOV     iw_Connection_No vw_Conn_No_Tmp
      -       vw_Conn_No_Tmp K1 vw_Conn_Bit_Pos
      ?OP6104 vwa_Rcv_Data_Byte[0] vd_Rcv_Pos
      SET     vba_Rcv[0]
      MPP
      RST     vb_Check_Input
; インデックスレジスタ一時退避
294   LD      SM400
      MOV     Z9 vw_ZTmp
      DMOV    D0 vd_DTmp1
      DMOV    D2 vd_DTmp2
      DMOV    D4 vd_DTmp3
      DMOV    D6 vd_DTmp4
      DMOV    D8 vd_DTmp5
      MOV     K0 Z9
      DMOV    K0 D0
      DMOV    K0 D2
      DMOV    K0 D4
      DMOV    K0 D6
      DMOV    K0 D8
; インデックスレジスタ値格納
339   LD      FB_ENO
      MPS
      ANI     vb_UDE
      MOV     vw_Start_IO_No_Tmp Z9
      SFR     Z9 K4
      MRD
      AND     vb_UDE
      MOV     K0 Z9
      MPP
      DMOV    vd_Rcv_Pos D0
; 全データ受信未完了時の再受信
374   LD      vb_Rcv_End
      MPS
      ANI     vb_Tmp_Error
      RST     vb_Rcv_End
      MPP
      SET     vba_Rcv[0]
; 超過データの復旧処理
396   LD      vb_Over_Recovery
      ?OP6104 vwa_Rcv_Data_Byte[0] D0
      MOV     vw_Over_Rcv_Len vw_Received_Len
      WTOB    vwa_Next_Rcv_Data[0] @D0 vw_Over_Rcv_Len
      DAND    vw_Received_Len H0FFFF vd_Calc_Dword
      D+      vd_Calc_Dword D0
414   LD      vb_Over_Recovery
      AND     vba_Rcv[0]
      MPS
      AND<>   vwa_Rcv_Data_Byte[0] H2
      MOV     K300 ERROR_ID
      SET     vb_Tmp_Error
      RST     vba_Rcv[0]
      MRD
      AND=    vwa_Rcv_Data_Byte[0] H2
      AND>=   vw_Received_Len K4
      -       vw_Received_Len vwa_Rcv_Data_Byte[3] vw_Over_Rcv_Len
      -       vw_Over_Rcv_Len K7 vw_Over_Rcv_Len
      MPS
      AND>=   vw_Over_Rcv_Len K0
      SET     vb_Fin_Rcv
      RST     vba_Rcv[0]
      MPP
      AND>    vw_Over_Rcv_Len K0
      SET     vb_Over_Rcv
      MPP
      RST     vb_Rcv_End
      RST     vb_Over_Recovery
; 受信処理開始
469   LD      vba_Rcv[0]
      MPS
      ANI     vb_UDE
      TEST    U0\G20485Z9 vw_Conn_Bit_Pos vb_Rcv_Flg
      MRD
      AND     vb_UDE
      TEST    SD1286 vw_Conn_Bit_Pos vb_Rcv_Flg
      MPP
      AND     vb_Rcv_Flg
      MPS
      ANI     vb_UDE
      ZP.BUFRCV "U0Z9" vw_Conn_No_Tmp vwa_Ctrl_Data[0] vwa_Rcv_Buf[0] vba_Rcv[1]
      MRD
      AND     vb_UDE
      SP.SOCRCV "U0" vw_Conn_No_Tmp vwa_Ctrl_Data[0] vwa_Rcv_Buf[0] vba_Rcv[1]
      MPP
      SET     vb_Receiving
524   LD      vba_Rcv[1]
      RST     vba_Rcv[0]
      MPS
      ANI     vba_Rcv[2]
      SET     vb_Rcv_End
      MRD
      AND     vba_Rcv[2]
      MOV     K301 ERROR_ID
      SET     vb_Tmp_Error
      MOV     vwa_Ctrl_Data[1] ow_UNT_ERR_CODE1
      SET     vb_Tmp_Unit_Error
      MPP
      RST     vb_Rcv_Flg
      RST     vb_Receiving
; 受信処理終了
557   LD      vb_Rcv_End
      +       vwa_Rcv_Buf[0] vw_Received_Len
      WTOB    vwa_Rcv_Buf[1] @D0 vwa_Rcv_Buf[0]
      DAND    vwa_Rcv_Buf[0] H0FFFF vd_Calc_Dword
      D+      vd_Calc_Dword D0
      MPS
      AND<>   vwa_Rcv_Data_Byte[0] H2
      MOV     K300 ERROR_ID
      SET     vb_Tmp_Error
      RST     vb_Rcv_End
      MPP
      AND=    vwa_Rcv_Data_Byte[0] H2
      AND>=   vw_Received_Len K4
      -       vw_Received_Len vwa_Rcv_Data_Byte[3] vw_Over_Rcv_Len
      -       vw_Over_Rcv_Len K7 vw_Over_Rcv_Len
      MPS
      AND>=   vw_Over_Rcv_Len K0
      SET     vb_Fin_Rcv
      MPP
      AND>    vw_Over_Rcv_Len K0
      SET     vb_Over_Rcv
; 全データ受信完了時処理
622   LD      vb_Fin_Rcv
      MOV     K7 vw_Trans_Len
      +       vwa_Rcv_Data_Byte[3] vw_Trans_Len
      -       vw_Trans_Len K3 vw_Etx_Ofs
      ?OP6104 vwa_Rcv_Data_Byte[0] D0
      DAND    vw_Etx_Ofs H0FFFF vd_Calc_Dword
      D+      vd_Calc_Dword D0
      MPS
      AND<>   @D0 H3
      MOV     K300 ERROR_ID
        [note] ETX値確認
      SET     vb_Tmp_Error
      MPP
      D+      K2 D0
        [note] CR値 =ETX値 + 2ワード
      MPS
      AND<>   @D0 H0D
      MOV     K300 ERROR_ID
        [note] CR値確認
      SET     vb_Tmp_Error
      MPP
      AND=    ERROR_ID K300
      RST     vb_Rcv_End
      RST     vb_Fin_Rcv
      RST     vb_Over_Rcv
      RST     vb_Over_Recovery
; 全データ受信完了時処理
718   LD      vb_Fin_Rcv
      RST     vb_Rcv_End
      -       vw_Trans_Len K2 vw_Sum_Len
        [note] SUMチェック処理
      WSUM    vwa_Rcv_Data_Byte[0] vwa_Chk_Sum[0] vw_Sum_Len
      DAND    H0FF vwa_Chk_Sum[0]
      ?OP6104 vwa_Rcv_Data_Byte[0] D0
      DAND    vw_Sum_Len H0FFFF vd_Calc_Dword
      D+      vd_Calc_Dword D0
      MOV     @D0 vw_Rcv_Sum
      MPS
      AND=    vw_Rcv_Sum vwa_Chk_Sum[0]
      SET     vb_Check_Cmd
      SET     vb_Tmp_OK
      MRD
      AND<>   vw_Rcv_Sum vwa_Chk_Sum[0]
      MOV     K300 ERROR_ID
      SET     vb_Tmp_Error
      MRD
      AND=    ERROR_ID K300
      RST     vb_Over_Rcv
      RST     vb_Over_Recovery
      MPP
      RST     vb_Fin_Rcv
; 複数コマンド同時受信時処理
799   LD      vb_Over_Rcv
      ?OP6104 vwa_Rcv_Data_Byte[0] D2
      DAND    vw_Trans_Len H0FFFF vd_Calc_Dword
      D+      vd_Calc_Dword D2
      BTOW    @D2 vwa_Next_Rcv_Data[0] vw_Over_Rcv_Len
      FMOV    K0 @D2 vw_Over_Rcv_Len
      SET     vb_Over_Recovery
      RST     vb_Over_Rcv
; 受信コマンドチェック
835   LD      vb_Check_Cmd
      ?OP6104 owa_RFID_UID D4
      ?OP6104 owa_RFID_Data D6
      ?OP6104 owa_RFID_UII D8
; 受信コマンドチェック
858   LD      vb_Check_Cmd
      MOV     vwa_Rcv_Data_Byte[1] ow_RFID_ID
        [note] 受信IDの設定
      MOV     K255 ow_RFID_Res_Type
        [note] 受信動作タイプの設定
      MPS
      AND=    vwa_Rcv_Data_Byte[2] H30
      MOV     K0 ow_RFID_Res_Type
      MRD
      AND=    vwa_Rcv_Data_Byte[2] H31
      MOV     K1 ow_RFID_Res_Type
      MRD
      AND=    vwa_Rcv_Data_Byte[2] H64
      MOV     K2 ow_RFID_Res_Type
      AND=    vwa_Rcv_Data_Byte[12] H42
      AND=    vwa_Rcv_Data_Byte[13] H52
      MOV     K5 ow_RFID_Res_Type
      MRD
      AND=    vwa_Rcv_Data_Byte[2] H4C
      MOV     K3 ow_RFID_Res_Type
      MRD
      AND=    vwa_Rcv_Data_Byte[2] H44
      MOV     K4 ow_RFID_Res_Type
      AND=    vwa_Rcv_Data_Byte[4] H42
      AND=    vwa_Rcv_Data_Byte[5] H52
      MOV     K5 ow_RFID_Res_Type
      MRD
      AND=    vwa_Rcv_Data_Byte[2] H49
      MOV     K6 ow_RFID_Res_Type
      MRD
      AND=    vwa_Rcv_Data_Byte[2] H6C
      AND=    vwa_Rcv_Data_Byte[4] H7
      MOV     K7 ow_RFID_Res_Type
      MPP
      AND=    vwa_Rcv_Data_Byte[2] H6C
      AND=    vwa_Rcv_Data_Byte[4] H8
      MOV     K8 ow_RFID_Res_Type
954   LD      vb_Check_Cmd
      MPS
      AND=    vwa_Rcv_Data_Byte[2] H30
      LD=     vwa_Rcv_Data_Byte[4] H1
      OR=     vwa_Rcv_Data_Byte[4] H2B
      ANB
      SET     vb_UID_Cmd
      MRD
      LD=     vwa_Rcv_Data_Byte[2] H49
      OR=     vwa_Rcv_Data_Byte[2] H4C
      OR=     vwa_Rcv_Data_Byte[2] H64
      ANB
      SET     vb_UID_Cmd
      MRD
      AND=    vwa_Rcv_Data_Byte[2] H6C
      SET     vb_EPC_Cmd
      MRD
      ANI     vb_UID_Cmd
      ANI     vb_EPC_Cmd
      SET     vb_Other_Cmd
      MPP
      RST     vb_Check_Cmd
; UIDを含むコマンドの出力ラベル設定
1017  LD      vb_UID_Cmd
      MOV     K8 ow_RFID_UID_Len
        [note] 受信UIDバイト数の設定
      MOV     vwa_Rcv_Data_Byte[3] ow_RFID_Data_Len
        [note] 受信バイト数の設定
      MPS
      AND<>   ow_RFID_Res_Type K0
      AND<>   ow_RFID_Res_Type K6
      -       ow_RFID_UID_Len ow_RFID_Data_Len
      MPP
      MOV     K0 ow_RFID_UII_Len
        [note] 受信UIIバイト数の設定
      AND=    vwa_Rcv_Data_Byte[2] H30
      BTOW    vwa_Rcv_Data_Byte[6] @D4 ow_RFID_UID_Len
      BTOW    vwa_Rcv_Data_Byte[4] @D6 ow_RFID_Data_Len
1084  LD      vb_UID_Cmd
      AND=    vwa_Rcv_Data_Byte[2] H49
      BTOW    vwa_Rcv_Data_Byte[5] @D4 ow_RFID_UID_Len
      BTOW    vwa_Rcv_Data_Byte[4] @D6 ow_RFID_Data_Len
1097  LD      vb_UID_Cmd
      MPS
      LD=     vwa_Rcv_Data_Byte[2] H4C
      OR=     vwa_Rcv_Data_Byte[2] H64
      ANB
      BTOW    vwa_Rcv_Data_Byte[4] @D4 ow_RFID_UID_Len
      BTOW    vwa_Rcv_Data_Byte[12] @D6 ow_RFID_Data_Len
      MPP
      RST     vb_UID_Cmd
; EPCコマンドの出力ラベル設定
1134  LD      vb_EPC_Cmd
      MOV     vwa_Rcv_Data_Byte[5] ow_RFID_UII_Len
      BTOW    vwa_Rcv_Data_Byte[6] @D8 ow_RFID_UII_Len
      AND=    vwa_Rcv_Data_Byte[4] H7
      MOV     K0 ow_RFID_UID_Len
        [note] 受信UIDバイト数の設定
      MOV     K0 ow_RFID_Data_Len
        [note] 受信バイト数の設定
1173  LD      vb_EPC_Cmd
      AND=    vwa_Rcv_Data_Byte[4] H8
      ?OP6104 vwa_Rcv_Data_Byte[6] D0
      DAND    ow_RFID_UII_Len H0FFFF vd_Calc_Dword
      D+      vd_Calc_Dword D0
      MOV     @D0 ow_RFID_Data_Len
      DINC    D0
      BTOW    @D0 @D6 ow_RFID_Data_Len
1198  LD      vb_EPC_Cmd
      AND=    vwa_Rcv_Data_Byte[4] H8
      +       ow_RFID_UII_Len ow_RFID_Data_Len vw_Chk_TID_Len
      +       K3 vw_Chk_TID_Len
      MPS
      AND>    vwa_Rcv_Data_Byte[3] vw_Chk_TID_Len
      DAND    ow_RFID_Data_Len H0FFFF vd_Calc_Dword
      D+      vd_Calc_Dword D0
      MOV     @D0 ow_RFID_UID_Len
      DINC    D0
      BTOW    @D0 @D4 ow_RFID_UID_Len
      MPP
      AND<=   vwa_Rcv_Data_Byte[3] vw_Chk_TID_Len
      MOV     K0 ow_RFID_UID_Len
1236  LD      vb_EPC_Cmd
      RST     vb_EPC_Cmd
; UIDを含まないコマンドの出力ラベル設定
1261  LD      vb_Other_Cmd
      MOV     K0 ow_RFID_UID_Len
        [note] 受信UIDバイト数の設定
      MPS
      AND=    vwa_Rcv_Data_Byte[2] H31
      MOV     K0 ow_RFID_Data_Len
        [note] 受信バイト数の設定
      MOV     vwa_Rcv_Data_Byte[4] ow_UNT_ERR_CODE1
      AND=    vwa_Rcv_Data_Byte[4] H5
      MOV     vwa_Rcv_Data_Byte[5] ow_UNT_ERR_CODE2
      MRD
      AND<>   vwa_Rcv_Data_Byte[2] H31
      MOV     vwa_Rcv_Data_Byte[3] ow_RFID_Data_Len
        [note] 受信バイト数の設定
      MRD
      AND<>   ow_RFID_Res_Type K255
      BTOW    vwa_Rcv_Data_Byte[4] @D6 ow_RFID_Data_Len
        [note] 受信データの設定
      MRD
      AND=    ow_RFID_Res_Type K255
      +       K7 ow_RFID_Data_Len
      BTOW    vwa_Rcv_Data_Byte[0] @D6 ow_RFID_Data_Len
        [note] 受信データの設定
      MPP
      MOV     K0 ow_RFID_UII_Len
        [note] 受信UIIバイト数の設定
      RST     vb_Other_Cmd
; インデックスレジスタ復帰処理
1392  LD      SM400
      MOV     vw_ZTmp Z9
      DMOV    D0 vd_Rcv_Pos
      DMOV    vd_DTmp1 D0
      DMOV    vd_DTmp2 D2
      DMOV    vd_DTmp3 D4
      DMOV    vd_DTmp4 D6
      DMOV    vd_DTmp5 D8
; FB終了処理
1414  LD      vb_Program_End
      MPS
      AND     vb_Tmp_OK
      PLS     FB_OK
      MRD
      AND     vb_Tmp_Error
      PLS     FB_ERROR
      MRD
      AND     vb_Tmp_Unit_Error
      PLS     ob_UNIT_ERROR
      MPP
      RST     vb_Tmp_OK
      RST     vb_Tmp_Error
      RST     vb_Tmp_Unit_Error
      RST     FB_ENO
      RST     vb_Program_End
      RST     vba_Rcv[0]
      RST     vba_Rcv[1]
      RST     vba_Rcv[2]
1451  LD      vb_Tmp_OK
      OR      vb_Tmp_Error
      OR      vb_Tmp_Unit_Error
      SET     vb_Program_End
END_FUNCTION_BLOCK

FUNCTION_BLOCK P+TAKAYA-TR3-E_WriteBytes  // WriteBytes
VAR_INPUT
  FB_EN : BOOL;  (* 実行命令 *)
  iw_Start_IO_No : INT;  (* 先頭I/ONo. *)
  iw_Connection_No : INT;  (* コネクションNo. *)
END_VAR
VAR_OUTPUT
  FB_OK : BOOL;  (* 正常完了 *)
  FB_ERROR : BOOL;  (* 異常完了フラグ *)
  ERROR_ID : INT;  (* エラーコード *)
  FB_ENO : BOOL;  (* 実行状態 *)
END_VAR
VAR
  vb_Program_Init : BOOL;  (* プログラム実行前初期化 *)
  vb_Check_Input : BOOL;  (* 入力範囲判定 *)
  vb_Tmp_Error : BOOL;  (* エラー内部フラグ *)
  vb_Tmp_OK : BOOL;  (* FB完了内部フラグ *)
  vw_Start_IO_No_Tmp : INT;  (* 先頭I/ONo.内部 *)
  vw_Connection_No_Tmp : INT;  (* コネクションNo.内部 *)
  vb_Tmp_Unit_Error : BOOL;  (* 機器エラー内部フラグ *)
  vb_Program_End : BOOL;  (* FB終了処理内部フラグ *)
END_VAR
VAR_OUTPUT
  ob_UNIT_ERROR : BOOL;  (* 機器異常完了フラグ *)
  ow_UNIT_ERR_CODE : INT;  (* 機器エラーコード *)
END_VAR
VAR
  vb_Send_Ready : BOOL;  (* 送信準備完了フラグ *)
  vba_Send : ARRAY [0..2] OF BOOL;  (* 送信処理フラグ *)
  vb_UDE : BOOL;  (* QnUDE(H)認識フラグ *)
  vb_Join_Byte : BOOL;  (* バイト単位結合 *)
  vwa_Buff_Send_Word : ARRAY [0..131] OF INT;  (* 送信バッファワード *)
END_VAR
VAR_INPUT
  iwa_UID : INT;  (* UID *)
  ib_UID_Flag : BOOL;  (* UID指定 *)
END_VAR
VAR
  vw_Write_Size_Tmp : INT;  (* 書き込みバイト数内部 *)
  vwa_UID_Tmp : ARRAY [0..7] OF INT;  (* UID内部 *)
END_VAR
VAR_INPUT
  iw_Write_Size : INT;  (* 書き込みバイト数 *)
  iw_Start_Blk_No : INT;  (* 書き込み開始ブロック番号 *)
END_VAR
VAR
  vw_Start_Blk_No_Tmp : INT;  (* 書き込み開始ブロック番号内部 *)
END_VAR
VAR_INPUT
  iwa_Write_Data : INT;  (* 書き込みデータ *)
END_VAR
VAR
  vw_RFID_Option_Tmp : INT;  (* RFタグオプション *)
  vw_Data_Len : INT;  (* データ長 *)
  vw_Send_Len : INT;  (* 送信数 *)
  vw_Send_Sum_Len : INT;  (* 送信SUM数 *)
  vwa_Send_Sum : ARRAY [0..1] OF INT;  (* 送信SUM合計値 *)
  vw_ZTmp : INT;  (* インデックスレジスタ一時退避 *)
  vwa_Write_Data_Tmp : ARRAY [0..249] OF INT;  (* 書き込みデータ内部 *)
  vwa_Control_Data : ARRAY [0..1] OF INT;  (* コントロールデータ *)
  vwa_Buff_Send_Byte : ARRAY [0..261] OF INT;  (* 送信バッファバイト *)
  vd_DTmp : DINT;  (* 内部Dデバイス *)
  vd_Calc_Dword : DINT;  (* ダブルワード計算用 *)
  vb_Sum_Calc : BOOL;  (* SUM計算開始フラグ *)
END_VAR
; ＊＊＊＊＊＊＊＊＊＊＊＊＊＊＊＊＊＊＊＊
; ＊FB名称:P+TAKAYA-TR3-E_WriteBytes
; ＊機能:WriteBytes
; ＊バージョン:Ver1.00A
; ＊＊＊＊＊＊＊＊＊＊＊＊＊＊＊＊＊＊＊＊
; FB非実行時接点OFF
98    LDI     FB_EN
      RST     vb_Program_Init
      RST     vb_Check_Input
      RST     vb_Join_Byte
      RST     vb_Sum_Calc
      RST     vb_Send_Ready
; FB実行開始時
118   LDP     FB_EN
      SET     FB_ENO
      SET     vb_Program_Init
; プログラム実行前初期化
138   LD      vb_Program_Init
      MOV     K0 ERROR_ID
      MOV     K0 ow_UNIT_ERR_CODE
      MOV     K0 vw_RFID_Option_Tmp
      MOV     K0 vw_Data_Len
      MOV     K0 vw_Send_Len
      MOV     K0 vw_Send_Sum_Len
      MOV     K0 vw_Start_Blk_No_Tmp
      MOV     K0 vw_Write_Size_Tmp
      DMOV    K0 vd_Calc_Dword
      FMOV    K0 vwa_UID_Tmp[0] K8
      FMOV    K0 vwa_Write_Data_Tmp[0] K250
      FMOV    K0 vwa_Buff_Send_Byte[0] K262
      FMOV    K0 vwa_Buff_Send_Word[0] K132
      FMOV    K0 vwa_Control_Data[0] K2
      FMOV    K0 vwa_Send_Sum[0] K2
      SET     vb_Check_Input
      RST     vb_Program_Init
; 入力範囲判定
195   LD      vb_Check_Input
      MPS
      AND=    H0FFFF iw_Start_IO_No
      SET     vb_UDE
      MRD
      ANI     vb_UDE
      LD<     iw_Connection_No K2
      OR=     iw_Connection_No K9
      OR>     iw_Connection_No K16
      ANB
      SET     vb_Tmp_Error
      MOV     K100 ERROR_ID
      MRD
      AND     vb_UDE
      LD<     iw_Connection_No K1
      OR>     iw_Connection_No K16
      ANB
      SET     vb_Tmp_Error
      MOV     K100 ERROR_ID
      MRD
      LD<     iw_Start_Blk_No K0
      OR>     iw_Start_Blk_No K255
      ANB
      SET     vb_Tmp_Error
      MOV     K114 ERROR_ID
      MRD
      LD      ib_UID_Flag
      LD<     iw_Write_Size K1
      OR>     iw_Write_Size K242
      ANB
      LDI     ib_UID_Flag
      LD<     iw_Write_Size K1
      OR>     iw_Write_Size K250
      ANB
      ORB
      ANB
      SET     vb_Tmp_Error
      MOV     K115 ERROR_ID
      MRD
      AND     ib_UID_Flag
      WTOB    iwa_UID vwa_UID_Tmp[0] K8
      MRD
      ANI     vb_Tmp_Error
      MOV     iw_Connection_No vw_Connection_No_Tmp
      MOV     iw_Start_IO_No vw_Start_IO_No_Tmp
      MOV     iw_Start_Blk_No vw_Start_Blk_No_Tmp
      MOV     iw_Write_Size vw_Write_Size_Tmp
      WTOB    iwa_Write_Data vwa_Write_Data_Tmp vw_Write_Size_Tmp
      SET     vba_Send[0]
      MPP
      RST     vb_Check_Input
; インデックスレジスタ一時退避
314   LD      SM400
      MOV     Z9 vw_ZTmp
      DMOV    D0 vd_DTmp
      MOV     K0 Z9
      DMOV    K0 D0
; インデックスレジスタ値格納
339   LD      FB_ENO
      MPS
      ANI     vb_UDE
      MOV     vw_Start_IO_No_Tmp Z9
      SFR     Z9 K4
      MPP
      AND     vb_UDE
      MOV     K0 Z9
; 送信フォーマット作成
367   LD      vba_Send[0]
      MOV     H2 vwa_Buff_Send_Byte[1]
      MOV     H0 vwa_Buff_Send_Byte[2]
      MOV     H78 vwa_Buff_Send_Byte[3]
      MPS
      AND     ib_UID_Flag
      +       vw_Write_Size_Tmp K12 vw_Data_Len
      MRD
      ANI     ib_UID_Flag
      +       vw_Write_Size_Tmp K4 vw_Data_Len
      MPP
      MOV     vw_Data_Len vwa_Buff_Send_Byte[4]
      MOV     H0A1 vwa_Buff_Send_Byte[5]
      MOV     vw_Start_Blk_No_Tmp vwa_Buff_Send_Byte[6]
      MOV     vw_Write_Size_Tmp vwa_Buff_Send_Byte[7]
396   LD      vba_Send[0]
      ?OP6104 vwa_Buff_Send_Byte[8] D0
      BMOV    vwa_Write_Data_Tmp[0] @D0 vw_Write_Size_Tmp
      DAND    vw_Write_Size_Tmp H0FFFF vd_Calc_Dword
      D+      vd_Calc_Dword D0
      MPS
      AND     ib_UID_Flag
      BSET    vw_RFID_Option_Tmp K0
      MPP
      MOV     vw_RFID_Option_Tmp @D0
      DINC    D0
      MPS
      AND     ib_UID_Flag
      BMOV    vwa_UID_Tmp[0] @D0 K8
      D+      K8 D0
      MPP
      MOV     H3 @D0
      D+      K2 D0
      MOV     H0D @D0
      SET     vb_Sum_Calc
      RST     vba_Send[0]
; SUMの計算
460   LD      vb_Sum_Calc
      ?OP6104 vwa_Buff_Send_Byte[1] D0
      +       vw_Data_Len K5 vw_Send_Sum_Len
      DAND    vw_Send_Sum_Len H0FFFF vd_Calc_Dword
      D+      vd_Calc_Dword D0
      WSUM    vwa_Buff_Send_Byte[1] vwa_Send_Sum[0] vw_Send_Sum_Len
      DAND    H0FF vwa_Send_Sum[0]
      MOV     vwa_Send_Sum[0] @D0
      SET     vb_Join_Byte
      RST     vb_Sum_Calc
; バイト単位データ結合
503   LD      vb_Join_Byte
      +       vw_Data_Len K7 vw_Send_Len
      BTOW    vwa_Buff_Send_Byte[1] vwa_Buff_Send_Word[1] vw_Send_Len
      MOV     vw_Send_Len vwa_Buff_Send_Word[0]
      SET     vb_Send_Ready
      RST     vb_Join_Byte
; 送信処理
524   LD      vb_Send_Ready
      MPS
      ANI     vb_UDE
      ZP.BUFSND "U0Z9" vw_Connection_No_Tmp vwa_Control_Data[0] vwa_Buff_Send_Word[0] vba_Send[1]
      MPP
      AND     vb_UDE
      SP.SOCSND "U0" vw_Connection_No_Tmp vwa_Control_Data[0] vwa_Buff_Send_Word[0] vba_Send[1]
; 正常完了かチェック
568   LD      vba_Send[1]
      MPS
      ANI     vba_Send[2]
      SET     vb_Tmp_OK
      MRD
      AND     vba_Send[2]
      MOV     K119 ERROR_ID
      SET     vb_Tmp_Error
      MOV     vwa_Control_Data[1] ow_UNIT_ERR_CODE
      SET     vb_Tmp_Unit_Error
      MPP
      RST     vb_Send_Ready
; インデックスレジスタ復帰処理
605   LD      SM400
      MOV     vw_ZTmp Z9
      DMOV    vd_DTmp D0
; FB完了処理
617   LD      vb_Program_End
      MPS
      AND     vb_Tmp_OK
      PLS     FB_OK
      MRD
      AND     vb_Tmp_Error
      PLS     FB_ERROR
      MRD
      AND     vb_Tmp_Unit_Error
      PLS     ob_UNIT_ERROR
      MPP
      RST     vb_Tmp_OK
      RST     vb_Tmp_Error
      RST     vb_Tmp_Unit_Error
      RST     FB_ENO
      RST     vb_Program_End
      RST     vba_Send[0]
      RST     vba_Send[1]
      RST     vba_Send[2]
      RST     vb_UDE
656   LD      vb_Tmp_OK
      OR      vb_Tmp_Error
      OR      vb_Tmp_Unit_Error
      SET     vb_Program_End
END_FUNCTION_BLOCK
